VERSION 5.7 ;
BUSBITCHARS "[]" ;
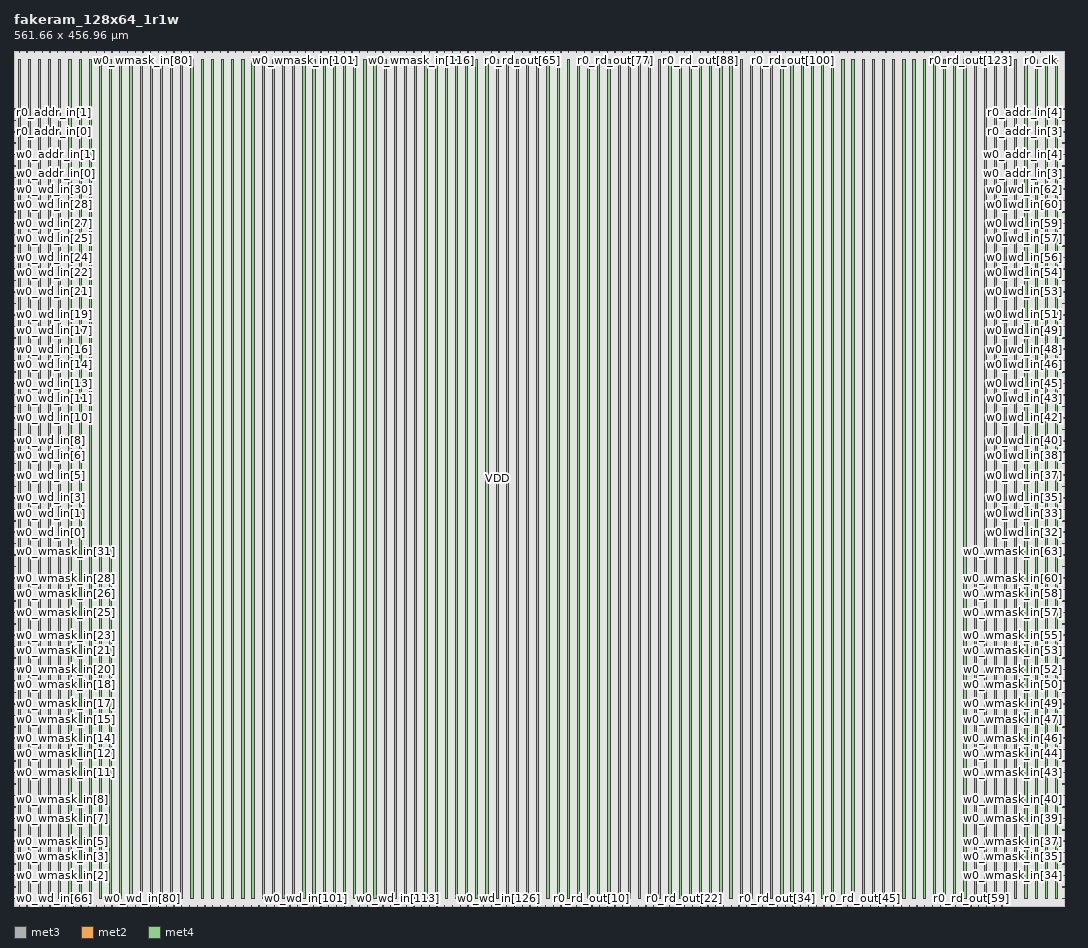
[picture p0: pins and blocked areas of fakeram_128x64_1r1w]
MACRO fakeram_128x64_1r1w
  FOREIGN fakeram_128x64_1r1w 0 0 ;
  SYMMETRY X Y R90 ;
  SIZE 561.660 BY 456.960 ;
  CLASS BLOCK ;
  PIN w0_wmask_in[0]
    DIRECTION INPUT ;
    USE SIGNAL ;
    SHAPE ABUTMENT ;
    PORT
      LAYER met3 ;
      RECT 0.000 3.930 0.900 4.230 ;
    END
  END w0_wmask_in[0]
  PIN w0_wmask_in[1]
    DIRECTION INPUT ;
    USE SIGNAL ;
    SHAPE ABUTMENT ;
    PORT
      LAYER met3 ;
      RECT 0.000 10.050 0.900 10.350 ;
    END
  END w0_wmask_in[1]
  PIN w0_wmask_in[2]
    DIRECTION INPUT ;
    USE SIGNAL ;
    SHAPE ABUTMENT ;
    PORT
      LAYER met3 ;
      RECT 0.000 16.170 0.900 16.470 ;
    END
  END w0_wmask_in[2]
  PIN w0_wmask_in[3]
    DIRECTION INPUT ;
    USE SIGNAL ;
    SHAPE ABUTMENT ;
    PORT
      LAYER met3 ;
      RECT 0.000 22.290 0.900 22.590 ;
    END
  END w0_wmask_in[3]
  PIN w0_wmask_in[4]
    DIRECTION INPUT ;
    USE SIGNAL ;
    SHAPE ABUTMENT ;
    PORT
      LAYER met3 ;
      RECT 0.000 28.410 0.900 28.710 ;
    END
  END w0_wmask_in[4]
  PIN w0_wmask_in[5]
    DIRECTION INPUT ;
    USE SIGNAL ;
    SHAPE ABUTMENT ;
    PORT
      LAYER met3 ;
      RECT 0.000 34.530 0.900 34.830 ;
    END
  END w0_wmask_in[5]
  PIN w0_wmask_in[6]
    DIRECTION INPUT ;
    USE SIGNAL ;
    SHAPE ABUTMENT ;
    PORT
      LAYER met3 ;
      RECT 0.000 40.650 0.900 40.950 ;
    END
  END w0_wmask_in[6]
  PIN w0_wmask_in[7]
    DIRECTION INPUT ;
    USE SIGNAL ;
    SHAPE ABUTMENT ;
    PORT
      LAYER met3 ;
      RECT 0.000 46.770 0.900 47.070 ;
    END
  END w0_wmask_in[7]
  PIN w0_wmask_in[8]
    DIRECTION INPUT ;
    USE SIGNAL ;
    SHAPE ABUTMENT ;
    PORT
      LAYER met3 ;
      RECT 0.000 52.890 0.900 53.190 ;
    END
  END w0_wmask_in[8]
  PIN w0_wmask_in[9]
    DIRECTION INPUT ;
    USE SIGNAL ;
    SHAPE ABUTMENT ;
    PORT
      LAYER met3 ;
      RECT 0.000 59.010 0.900 59.310 ;
    END
  END w0_wmask_in[9]
  PIN w0_wmask_in[10]
    DIRECTION INPUT ;
    USE SIGNAL ;
    SHAPE ABUTMENT ;
    PORT
      LAYER met3 ;
      RECT 0.000 65.130 0.900 65.430 ;
    END
  END w0_wmask_in[10]
  PIN w0_wmask_in[11]
    DIRECTION INPUT ;
    USE SIGNAL ;
    SHAPE ABUTMENT ;
    PORT
      LAYER met3 ;
      RECT 0.000 71.250 0.900 71.550 ;
    END
  END w0_wmask_in[11]
  PIN w0_wmask_in[12]
    DIRECTION INPUT ;
    USE SIGNAL ;
    SHAPE ABUTMENT ;
    PORT
      LAYER met3 ;
      RECT 0.000 77.370 0.900 77.670 ;
    END
  END w0_wmask_in[12]
  PIN w0_wmask_in[13]
    DIRECTION INPUT ;
    USE SIGNAL ;
    SHAPE ABUTMENT ;
    PORT
      LAYER met3 ;
      RECT 0.000 83.490 0.900 83.790 ;
    END
  END w0_wmask_in[13]
  PIN w0_wmask_in[14]
    DIRECTION INPUT ;
    USE SIGNAL ;
    SHAPE ABUTMENT ;
    PORT
      LAYER met3 ;
      RECT 0.000 89.610 0.900 89.910 ;
    END
  END w0_wmask_in[14]
  PIN w0_wmask_in[15]
    DIRECTION INPUT ;
    USE SIGNAL ;
    SHAPE ABUTMENT ;
    PORT
      LAYER met3 ;
      RECT 0.000 95.730 0.900 96.030 ;
    END
  END w0_wmask_in[15]
  PIN w0_wmask_in[16]
    DIRECTION INPUT ;
    USE SIGNAL ;
    SHAPE ABUTMENT ;
    PORT
      LAYER met3 ;
      RECT 0.000 101.850 0.900 102.150 ;
    END
  END w0_wmask_in[16]
  PIN w0_wmask_in[17]
    DIRECTION INPUT ;
    USE SIGNAL ;
    SHAPE ABUTMENT ;
    PORT
      LAYER met3 ;
      RECT 0.000 107.970 0.900 108.270 ;
    END
  END w0_wmask_in[17]
  PIN w0_wmask_in[18]
    DIRECTION INPUT ;
    USE SIGNAL ;
    SHAPE ABUTMENT ;
    PORT
      LAYER met3 ;
      RECT 0.000 114.090 0.900 114.390 ;
    END
  END w0_wmask_in[18]
  PIN w0_wmask_in[19]
    DIRECTION INPUT ;
    USE SIGNAL ;
    SHAPE ABUTMENT ;
    PORT
      LAYER met3 ;
      RECT 0.000 120.210 0.900 120.510 ;
    END
  END w0_wmask_in[19]
  PIN w0_wmask_in[20]
    DIRECTION INPUT ;
    USE SIGNAL ;
    SHAPE ABUTMENT ;
    PORT
      LAYER met3 ;
      RECT 0.000 126.330 0.900 126.630 ;
    END
  END w0_wmask_in[20]
  PIN w0_wmask_in[21]
    DIRECTION INPUT ;
    USE SIGNAL ;
    SHAPE ABUTMENT ;
    PORT
      LAYER met3 ;
      RECT 0.000 132.450 0.900 132.750 ;
    END
  END w0_wmask_in[21]
  PIN w0_wmask_in[22]
    DIRECTION INPUT ;
    USE SIGNAL ;
    SHAPE ABUTMENT ;
    PORT
      LAYER met3 ;
      RECT 0.000 138.570 0.900 138.870 ;
    END
  END w0_wmask_in[22]
  PIN w0_wmask_in[23]
    DIRECTION INPUT ;
    USE SIGNAL ;
    SHAPE ABUTMENT ;
    PORT
      LAYER met3 ;
      RECT 0.000 144.690 0.900 144.990 ;
    END
  END w0_wmask_in[23]
  PIN w0_wmask_in[24]
    DIRECTION INPUT ;
    USE SIGNAL ;
    SHAPE ABUTMENT ;
    PORT
      LAYER met3 ;
      RECT 0.000 150.810 0.900 151.110 ;
    END
  END w0_wmask_in[24]
  PIN w0_wmask_in[25]
    DIRECTION INPUT ;
    USE SIGNAL ;
    SHAPE ABUTMENT ;
    PORT
      LAYER met3 ;
      RECT 0.000 156.930 0.900 157.230 ;
    END
  END w0_wmask_in[25]
  PIN w0_wmask_in[26]
    DIRECTION INPUT ;
    USE SIGNAL ;
    SHAPE ABUTMENT ;
    PORT
      LAYER met3 ;
      RECT 0.000 163.050 0.900 163.350 ;
    END
  END w0_wmask_in[26]
  PIN w0_wmask_in[27]
    DIRECTION INPUT ;
    USE SIGNAL ;
    SHAPE ABUTMENT ;
    PORT
      LAYER met3 ;
      RECT 0.000 169.170 0.900 169.470 ;
    END
  END w0_wmask_in[27]
  PIN w0_wmask_in[28]
    DIRECTION INPUT ;
    USE SIGNAL ;
    SHAPE ABUTMENT ;
    PORT
      LAYER met3 ;
      RECT 0.000 175.290 0.900 175.590 ;
    END
  END w0_wmask_in[28]
  PIN w0_wmask_in[29]
    DIRECTION INPUT ;
    USE SIGNAL ;
    SHAPE ABUTMENT ;
    PORT
      LAYER met3 ;
      RECT 0.000 181.410 0.900 181.710 ;
    END
  END w0_wmask_in[29]
  PIN w0_wmask_in[30]
    DIRECTION INPUT ;
    USE SIGNAL ;
    SHAPE ABUTMENT ;
    PORT
      LAYER met3 ;
      RECT 0.000 187.530 0.900 187.830 ;
    END
  END w0_wmask_in[30]
  PIN w0_wmask_in[31]
    DIRECTION INPUT ;
    USE SIGNAL ;
    SHAPE ABUTMENT ;
    PORT
      LAYER met3 ;
      RECT 0.000 193.650 0.900 193.950 ;
    END
  END w0_wmask_in[31]
  PIN w0_wmask_in[32]
    DIRECTION INPUT ;
    USE SIGNAL ;
    SHAPE ABUTMENT ;
    PORT
      LAYER met3 ;
      RECT 560.760 3.930 561.660 4.230 ;
    END
  END w0_wmask_in[32]
  PIN w0_wmask_in[33]
    DIRECTION INPUT ;
    USE SIGNAL ;
    SHAPE ABUTMENT ;
    PORT
      LAYER met3 ;
      RECT 560.760 10.050 561.660 10.350 ;
    END
  END w0_wmask_in[33]
  PIN w0_wmask_in[34]
    DIRECTION INPUT ;
    USE SIGNAL ;
    SHAPE ABUTMENT ;
    PORT
      LAYER met3 ;
      RECT 560.760 16.170 561.660 16.470 ;
    END
  END w0_wmask_in[34]
  PIN w0_wmask_in[35]
    DIRECTION INPUT ;
    USE SIGNAL ;
    SHAPE ABUTMENT ;
    PORT
      LAYER met3 ;
      RECT 560.760 22.290 561.660 22.590 ;
    END
  END w0_wmask_in[35]
  PIN w0_wmask_in[36]
    DIRECTION INPUT ;
    USE SIGNAL ;
    SHAPE ABUTMENT ;
    PORT
      LAYER met3 ;
      RECT 560.760 28.410 561.660 28.710 ;
    END
  END w0_wmask_in[36]
  PIN w0_wmask_in[37]
    DIRECTION INPUT ;
    USE SIGNAL ;
    SHAPE ABUTMENT ;
    PORT
      LAYER met3 ;
      RECT 560.760 34.530 561.660 34.830 ;
    END
  END w0_wmask_in[37]
  PIN w0_wmask_in[38]
    DIRECTION INPUT ;
    USE SIGNAL ;
    SHAPE ABUTMENT ;
    PORT
      LAYER met3 ;
      RECT 560.760 40.650 561.660 40.950 ;
    END
  END w0_wmask_in[38]
  PIN w0_wmask_in[39]
    DIRECTION INPUT ;
    USE SIGNAL ;
    SHAPE ABUTMENT ;
    PORT
      LAYER met3 ;
      RECT 560.760 46.770 561.660 47.070 ;
    END
  END w0_wmask_in[39]
  PIN w0_wmask_in[40]
    DIRECTION INPUT ;
    USE SIGNAL ;
    SHAPE ABUTMENT ;
    PORT
      LAYER met3 ;
      RECT 560.760 52.890 561.660 53.190 ;
    END
  END w0_wmask_in[40]
  PIN w0_wmask_in[41]
    DIRECTION INPUT ;
    USE SIGNAL ;
    SHAPE ABUTMENT ;
    PORT
      LAYER met3 ;
      RECT 560.760 59.010 561.660 59.310 ;
    END
  END w0_wmask_in[41]
  PIN w0_wmask_in[42]
    DIRECTION INPUT ;
    USE SIGNAL ;
    SHAPE ABUTMENT ;
    PORT
      LAYER met3 ;
      RECT 560.760 65.130 561.660 65.430 ;
    END
  END w0_wmask_in[42]
  PIN w0_wmask_in[43]
    DIRECTION INPUT ;
    USE SIGNAL ;
    SHAPE ABUTMENT ;
    PORT
      LAYER met3 ;
      RECT 560.760 71.250 561.660 71.550 ;
    END
  END w0_wmask_in[43]
  PIN w0_wmask_in[44]
    DIRECTION INPUT ;
    USE SIGNAL ;
    SHAPE ABUTMENT ;
    PORT
      LAYER met3 ;
      RECT 560.760 77.370 561.660 77.670 ;
    END
  END w0_wmask_in[44]
  PIN w0_wmask_in[45]
    DIRECTION INPUT ;
    USE SIGNAL ;
    SHAPE ABUTMENT ;
    PORT
      LAYER met3 ;
      RECT 560.760 83.490 561.660 83.790 ;
    END
  END w0_wmask_in[45]
  PIN w0_wmask_in[46]
    DIRECTION INPUT ;
    USE SIGNAL ;
    SHAPE ABUTMENT ;
    PORT
      LAYER met3 ;
      RECT 560.760 89.610 561.660 89.910 ;
    END
  END w0_wmask_in[46]
  PIN w0_wmask_in[47]
    DIRECTION INPUT ;
    USE SIGNAL ;
    SHAPE ABUTMENT ;
    PORT
      LAYER met3 ;
      RECT 560.760 95.730 561.660 96.030 ;
    END
  END w0_wmask_in[47]
  PIN w0_wmask_in[48]
    DIRECTION INPUT ;
    USE SIGNAL ;
    SHAPE ABUTMENT ;
    PORT
      LAYER met3 ;
      RECT 560.760 101.850 561.660 102.150 ;
    END
  END w0_wmask_in[48]
  PIN w0_wmask_in[49]
    DIRECTION INPUT ;
    USE SIGNAL ;
    SHAPE ABUTMENT ;
    PORT
      LAYER met3 ;
      RECT 560.760 107.970 561.660 108.270 ;
    END
  END w0_wmask_in[49]
  PIN w0_wmask_in[50]
    DIRECTION INPUT ;
    USE SIGNAL ;
    SHAPE ABUTMENT ;
    PORT
      LAYER met3 ;
      RECT 560.760 114.090 561.660 114.390 ;
    END
  END w0_wmask_in[50]
  PIN w0_wmask_in[51]
    DIRECTION INPUT ;
    USE SIGNAL ;
    SHAPE ABUTMENT ;
    PORT
      LAYER met3 ;
      RECT 560.760 120.210 561.660 120.510 ;
    END
  END w0_wmask_in[51]
  PIN w0_wmask_in[52]
    DIRECTION INPUT ;
    USE SIGNAL ;
    SHAPE ABUTMENT ;
    PORT
      LAYER met3 ;
      RECT 560.760 126.330 561.660 126.630 ;
    END
  END w0_wmask_in[52]
  PIN w0_wmask_in[53]
    DIRECTION INPUT ;
    USE SIGNAL ;
    SHAPE ABUTMENT ;
    PORT
      LAYER met3 ;
      RECT 560.760 132.450 561.660 132.750 ;
    END
  END w0_wmask_in[53]
  PIN w0_wmask_in[54]
    DIRECTION INPUT ;
    USE SIGNAL ;
    SHAPE ABUTMENT ;
    PORT
      LAYER met3 ;
      RECT 560.760 138.570 561.660 138.870 ;
    END
  END w0_wmask_in[54]
  PIN w0_wmask_in[55]
    DIRECTION INPUT ;
    USE SIGNAL ;
    SHAPE ABUTMENT ;
    PORT
      LAYER met3 ;
      RECT 560.760 144.690 561.660 144.990 ;
    END
  END w0_wmask_in[55]
  PIN w0_wmask_in[56]
    DIRECTION INPUT ;
    USE SIGNAL ;
    SHAPE ABUTMENT ;
    PORT
      LAYER met3 ;
      RECT 560.760 150.810 561.660 151.110 ;
    END
  END w0_wmask_in[56]
  PIN w0_wmask_in[57]
    DIRECTION INPUT ;
    USE SIGNAL ;
    SHAPE ABUTMENT ;
    PORT
      LAYER met3 ;
      RECT 560.760 156.930 561.660 157.230 ;
    END
  END w0_wmask_in[57]
  PIN w0_wmask_in[58]
    DIRECTION INPUT ;
    USE SIGNAL ;
    SHAPE ABUTMENT ;
    PORT
      LAYER met3 ;
      RECT 560.760 163.050 561.660 163.350 ;
    END
  END w0_wmask_in[58]
  PIN w0_wmask_in[59]
    DIRECTION INPUT ;
    USE SIGNAL ;
    SHAPE ABUTMENT ;
    PORT
      LAYER met3 ;
      RECT 560.760 169.170 561.660 169.470 ;
    END
  END w0_wmask_in[59]
  PIN w0_wmask_in[60]
    DIRECTION INPUT ;
    USE SIGNAL ;
    SHAPE ABUTMENT ;
    PORT
      LAYER met3 ;
      RECT 560.760 175.290 561.660 175.590 ;
    END
  END w0_wmask_in[60]
  PIN w0_wmask_in[61]
    DIRECTION INPUT ;
    USE SIGNAL ;
    SHAPE ABUTMENT ;
    PORT
      LAYER met3 ;
      RECT 560.760 181.410 561.660 181.710 ;
    END
  END w0_wmask_in[61]
  PIN w0_wmask_in[62]
    DIRECTION INPUT ;
    USE SIGNAL ;
    SHAPE ABUTMENT ;
    PORT
      LAYER met3 ;
      RECT 560.760 187.530 561.660 187.830 ;
    END
  END w0_wmask_in[62]
  PIN w0_wmask_in[63]
    DIRECTION INPUT ;
    USE SIGNAL ;
    SHAPE ABUTMENT ;
    PORT
      LAYER met3 ;
      RECT 560.760 193.650 561.660 193.950 ;
    END
  END w0_wmask_in[63]
  PIN w0_wmask_in[64]
    DIRECTION INPUT ;
    USE SIGNAL ;
    SHAPE ABUTMENT ;
    PORT
      LAYER met2 ;
      RECT 2.690 456.540 2.830 456.960 ;
    END
  END w0_wmask_in[64]
  PIN w0_wmask_in[65]
    DIRECTION INPUT ;
    USE SIGNAL ;
    SHAPE ABUTMENT ;
    PORT
      LAYER met2 ;
      RECT 6.830 456.540 6.970 456.960 ;
    END
  END w0_wmask_in[65]
  PIN w0_wmask_in[66]
    DIRECTION INPUT ;
    USE SIGNAL ;
    SHAPE ABUTMENT ;
    PORT
      LAYER met2 ;
      RECT 10.970 456.540 11.110 456.960 ;
    END
  END w0_wmask_in[66]
  PIN w0_wmask_in[67]
    DIRECTION INPUT ;
    USE SIGNAL ;
    SHAPE ABUTMENT ;
    PORT
      LAYER met2 ;
      RECT 15.110 456.540 15.250 456.960 ;
    END
  END w0_wmask_in[67]
  PIN w0_wmask_in[68]
    DIRECTION INPUT ;
    USE SIGNAL ;
    SHAPE ABUTMENT ;
    PORT
      LAYER met2 ;
      RECT 19.250 456.540 19.390 456.960 ;
    END
  END w0_wmask_in[68]
  PIN w0_wmask_in[69]
    DIRECTION INPUT ;
    USE SIGNAL ;
    SHAPE ABUTMENT ;
    PORT
      LAYER met2 ;
      RECT 23.390 456.540 23.530 456.960 ;
    END
  END w0_wmask_in[69]
  PIN w0_wmask_in[70]
    DIRECTION INPUT ;
    USE SIGNAL ;
    SHAPE ABUTMENT ;
    PORT
      LAYER met2 ;
      RECT 27.530 456.540 27.670 456.960 ;
    END
  END w0_wmask_in[70]
  PIN w0_wmask_in[71]
    DIRECTION INPUT ;
    USE SIGNAL ;
    SHAPE ABUTMENT ;
    PORT
      LAYER met2 ;
      RECT 31.670 456.540 31.810 456.960 ;
    END
  END w0_wmask_in[71]
  PIN w0_wmask_in[72]
    DIRECTION INPUT ;
    USE SIGNAL ;
    SHAPE ABUTMENT ;
    PORT
      LAYER met2 ;
      RECT 35.810 456.540 35.950 456.960 ;
    END
  END w0_wmask_in[72]
  PIN w0_wmask_in[73]
    DIRECTION INPUT ;
    USE SIGNAL ;
    SHAPE ABUTMENT ;
    PORT
      LAYER met2 ;
      RECT 39.950 456.540 40.090 456.960 ;
    END
  END w0_wmask_in[73]
  PIN w0_wmask_in[74]
    DIRECTION INPUT ;
    USE SIGNAL ;
    SHAPE ABUTMENT ;
    PORT
      LAYER met2 ;
      RECT 44.090 456.540 44.230 456.960 ;
    END
  END w0_wmask_in[74]
  PIN w0_wmask_in[75]
    DIRECTION INPUT ;
    USE SIGNAL ;
    SHAPE ABUTMENT ;
    PORT
      LAYER met2 ;
      RECT 48.230 456.540 48.370 456.960 ;
    END
  END w0_wmask_in[75]
  PIN w0_wmask_in[76]
    DIRECTION INPUT ;
    USE SIGNAL ;
    SHAPE ABUTMENT ;
    PORT
      LAYER met2 ;
      RECT 52.370 456.540 52.510 456.960 ;
    END
  END w0_wmask_in[76]
  PIN w0_wmask_in[77]
    DIRECTION INPUT ;
    USE SIGNAL ;
    SHAPE ABUTMENT ;
    PORT
      LAYER met2 ;
      RECT 56.510 456.540 56.650 456.960 ;
    END
  END w0_wmask_in[77]
  PIN w0_wmask_in[78]
    DIRECTION INPUT ;
    USE SIGNAL ;
    SHAPE ABUTMENT ;
    PORT
      LAYER met2 ;
      RECT 60.650 456.540 60.790 456.960 ;
    END
  END w0_wmask_in[78]
  PIN w0_wmask_in[79]
    DIRECTION INPUT ;
    USE SIGNAL ;
    SHAPE ABUTMENT ;
    PORT
      LAYER met2 ;
      RECT 64.790 456.540 64.930 456.960 ;
    END
  END w0_wmask_in[79]
  PIN w0_wmask_in[80]
    DIRECTION INPUT ;
    USE SIGNAL ;
    SHAPE ABUTMENT ;
    PORT
      LAYER met2 ;
      RECT 68.930 456.540 69.070 456.960 ;
    END
  END w0_wmask_in[80]
  PIN w0_wmask_in[81]
    DIRECTION INPUT ;
    USE SIGNAL ;
    SHAPE ABUTMENT ;
    PORT
      LAYER met2 ;
      RECT 73.070 456.540 73.210 456.960 ;
    END
  END w0_wmask_in[81]
  PIN w0_wmask_in[82]
    DIRECTION INPUT ;
    USE SIGNAL ;
    SHAPE ABUTMENT ;
    PORT
      LAYER met2 ;
      RECT 77.210 456.540 77.350 456.960 ;
    END
  END w0_wmask_in[82]
  PIN w0_wmask_in[83]
    DIRECTION INPUT ;
    USE SIGNAL ;
    SHAPE ABUTMENT ;
    PORT
      LAYER met2 ;
      RECT 81.350 456.540 81.490 456.960 ;
    END
  END w0_wmask_in[83]
  PIN w0_wmask_in[84]
    DIRECTION INPUT ;
    USE SIGNAL ;
    SHAPE ABUTMENT ;
    PORT
      LAYER met2 ;
      RECT 85.490 456.540 85.630 456.960 ;
    END
  END w0_wmask_in[84]
  PIN w0_wmask_in[85]
    DIRECTION INPUT ;
    USE SIGNAL ;
    SHAPE ABUTMENT ;
    PORT
      LAYER met2 ;
      RECT 89.630 456.540 89.770 456.960 ;
    END
  END w0_wmask_in[85]
  PIN w0_wmask_in[86]
    DIRECTION INPUT ;
    USE SIGNAL ;
    SHAPE ABUTMENT ;
    PORT
      LAYER met2 ;
      RECT 93.770 456.540 93.910 456.960 ;
    END
  END w0_wmask_in[86]
  PIN w0_wmask_in[87]
    DIRECTION INPUT ;
    USE SIGNAL ;
    SHAPE ABUTMENT ;
    PORT
      LAYER met2 ;
      RECT 97.910 456.540 98.050 456.960 ;
    END
  END w0_wmask_in[87]
  PIN w0_wmask_in[88]
    DIRECTION INPUT ;
    USE SIGNAL ;
    SHAPE ABUTMENT ;
    PORT
      LAYER met2 ;
      RECT 102.050 456.540 102.190 456.960 ;
    END
  END w0_wmask_in[88]
  PIN w0_wmask_in[89]
    DIRECTION INPUT ;
    USE SIGNAL ;
    SHAPE ABUTMENT ;
    PORT
      LAYER met2 ;
      RECT 106.190 456.540 106.330 456.960 ;
    END
  END w0_wmask_in[89]
  PIN w0_wmask_in[90]
    DIRECTION INPUT ;
    USE SIGNAL ;
    SHAPE ABUTMENT ;
    PORT
      LAYER met2 ;
      RECT 110.330 456.540 110.470 456.960 ;
    END
  END w0_wmask_in[90]
  PIN w0_wmask_in[91]
    DIRECTION INPUT ;
    USE SIGNAL ;
    SHAPE ABUTMENT ;
    PORT
      LAYER met2 ;
      RECT 114.470 456.540 114.610 456.960 ;
    END
  END w0_wmask_in[91]
  PIN w0_wmask_in[92]
    DIRECTION INPUT ;
    USE SIGNAL ;
    SHAPE ABUTMENT ;
    PORT
      LAYER met2 ;
      RECT 118.610 456.540 118.750 456.960 ;
    END
  END w0_wmask_in[92]
  PIN w0_wmask_in[93]
    DIRECTION INPUT ;
    USE SIGNAL ;
    SHAPE ABUTMENT ;
    PORT
      LAYER met2 ;
      RECT 122.750 456.540 122.890 456.960 ;
    END
  END w0_wmask_in[93]
  PIN w0_wmask_in[94]
    DIRECTION INPUT ;
    USE SIGNAL ;
    SHAPE ABUTMENT ;
    PORT
      LAYER met2 ;
      RECT 126.890 456.540 127.030 456.960 ;
    END
  END w0_wmask_in[94]
  PIN w0_wmask_in[95]
    DIRECTION INPUT ;
    USE SIGNAL ;
    SHAPE ABUTMENT ;
    PORT
      LAYER met2 ;
      RECT 131.030 456.540 131.170 456.960 ;
    END
  END w0_wmask_in[95]
  PIN w0_wmask_in[96]
    DIRECTION INPUT ;
    USE SIGNAL ;
    SHAPE ABUTMENT ;
    PORT
      LAYER met2 ;
      RECT 135.170 456.540 135.310 456.960 ;
    END
  END w0_wmask_in[96]
  PIN w0_wmask_in[97]
    DIRECTION INPUT ;
    USE SIGNAL ;
    SHAPE ABUTMENT ;
    PORT
      LAYER met2 ;
      RECT 139.310 456.540 139.450 456.960 ;
    END
  END w0_wmask_in[97]
  PIN w0_wmask_in[98]
    DIRECTION INPUT ;
    USE SIGNAL ;
    SHAPE ABUTMENT ;
    PORT
      LAYER met2 ;
      RECT 143.450 456.540 143.590 456.960 ;
    END
  END w0_wmask_in[98]
  PIN w0_wmask_in[99]
    DIRECTION INPUT ;
    USE SIGNAL ;
    SHAPE ABUTMENT ;
    PORT
      LAYER met2 ;
      RECT 147.590 456.540 147.730 456.960 ;
    END
  END w0_wmask_in[99]
  PIN w0_wmask_in[100]
    DIRECTION INPUT ;
    USE SIGNAL ;
    SHAPE ABUTMENT ;
    PORT
      LAYER met2 ;
      RECT 151.730 456.540 151.870 456.960 ;
    END
  END w0_wmask_in[100]
  PIN w0_wmask_in[101]
    DIRECTION INPUT ;
    USE SIGNAL ;
    SHAPE ABUTMENT ;
    PORT
      LAYER met2 ;
      RECT 155.870 456.540 156.010 456.960 ;
    END
  END w0_wmask_in[101]
  PIN w0_wmask_in[102]
    DIRECTION INPUT ;
    USE SIGNAL ;
    SHAPE ABUTMENT ;
    PORT
      LAYER met2 ;
      RECT 160.010 456.540 160.150 456.960 ;
    END
  END w0_wmask_in[102]
  PIN w0_wmask_in[103]
    DIRECTION INPUT ;
    USE SIGNAL ;
    SHAPE ABUTMENT ;
    PORT
      LAYER met2 ;
      RECT 164.150 456.540 164.290 456.960 ;
    END
  END w0_wmask_in[103]
  PIN w0_wmask_in[104]
    DIRECTION INPUT ;
    USE SIGNAL ;
    SHAPE ABUTMENT ;
    PORT
      LAYER met2 ;
      RECT 168.290 456.540 168.430 456.960 ;
    END
  END w0_wmask_in[104]
  PIN w0_wmask_in[105]
    DIRECTION INPUT ;
    USE SIGNAL ;
    SHAPE ABUTMENT ;
    PORT
      LAYER met2 ;
      RECT 172.430 456.540 172.570 456.960 ;
    END
  END w0_wmask_in[105]
  PIN w0_wmask_in[106]
    DIRECTION INPUT ;
    USE SIGNAL ;
    SHAPE ABUTMENT ;
    PORT
      LAYER met2 ;
      RECT 176.570 456.540 176.710 456.960 ;
    END
  END w0_wmask_in[106]
  PIN w0_wmask_in[107]
    DIRECTION INPUT ;
    USE SIGNAL ;
    SHAPE ABUTMENT ;
    PORT
      LAYER met2 ;
      RECT 180.710 456.540 180.850 456.960 ;
    END
  END w0_wmask_in[107]
  PIN w0_wmask_in[108]
    DIRECTION INPUT ;
    USE SIGNAL ;
    SHAPE ABUTMENT ;
    PORT
      LAYER met2 ;
      RECT 184.850 456.540 184.990 456.960 ;
    END
  END w0_wmask_in[108]
  PIN w0_wmask_in[109]
    DIRECTION INPUT ;
    USE SIGNAL ;
    SHAPE ABUTMENT ;
    PORT
      LAYER met2 ;
      RECT 188.990 456.540 189.130 456.960 ;
    END
  END w0_wmask_in[109]
  PIN w0_wmask_in[110]
    DIRECTION INPUT ;
    USE SIGNAL ;
    SHAPE ABUTMENT ;
    PORT
      LAYER met2 ;
      RECT 193.130 456.540 193.270 456.960 ;
    END
  END w0_wmask_in[110]
  PIN w0_wmask_in[111]
    DIRECTION INPUT ;
    USE SIGNAL ;
    SHAPE ABUTMENT ;
    PORT
      LAYER met2 ;
      RECT 197.270 456.540 197.410 456.960 ;
    END
  END w0_wmask_in[111]
  PIN w0_wmask_in[112]
    DIRECTION INPUT ;
    USE SIGNAL ;
    SHAPE ABUTMENT ;
    PORT
      LAYER met2 ;
      RECT 201.410 456.540 201.550 456.960 ;
    END
  END w0_wmask_in[112]
  PIN w0_wmask_in[113]
    DIRECTION INPUT ;
    USE SIGNAL ;
    SHAPE ABUTMENT ;
    PORT
      LAYER met2 ;
      RECT 205.550 456.540 205.690 456.960 ;
    END
  END w0_wmask_in[113]
  PIN w0_wmask_in[114]
    DIRECTION INPUT ;
    USE SIGNAL ;
    SHAPE ABUTMENT ;
    PORT
      LAYER met2 ;
      RECT 209.690 456.540 209.830 456.960 ;
    END
  END w0_wmask_in[114]
  PIN w0_wmask_in[115]
    DIRECTION INPUT ;
    USE SIGNAL ;
    SHAPE ABUTMENT ;
    PORT
      LAYER met2 ;
      RECT 213.830 456.540 213.970 456.960 ;
    END
  END w0_wmask_in[115]
  PIN w0_wmask_in[116]
    DIRECTION INPUT ;
    USE SIGNAL ;
    SHAPE ABUTMENT ;
    PORT
      LAYER met2 ;
      RECT 217.970 456.540 218.110 456.960 ;
    END
  END w0_wmask_in[116]
  PIN w0_wmask_in[117]
    DIRECTION INPUT ;
    USE SIGNAL ;
    SHAPE ABUTMENT ;
    PORT
      LAYER met2 ;
      RECT 222.110 456.540 222.250 456.960 ;
    END
  END w0_wmask_in[117]
  PIN w0_wmask_in[118]
    DIRECTION INPUT ;
    USE SIGNAL ;
    SHAPE ABUTMENT ;
    PORT
      LAYER met2 ;
      RECT 226.250 456.540 226.390 456.960 ;
    END
  END w0_wmask_in[118]
  PIN w0_wmask_in[119]
    DIRECTION INPUT ;
    USE SIGNAL ;
    SHAPE ABUTMENT ;
    PORT
      LAYER met2 ;
      RECT 230.390 456.540 230.530 456.960 ;
    END
  END w0_wmask_in[119]
  PIN w0_wmask_in[120]
    DIRECTION INPUT ;
    USE SIGNAL ;
    SHAPE ABUTMENT ;
    PORT
      LAYER met2 ;
      RECT 234.530 456.540 234.670 456.960 ;
    END
  END w0_wmask_in[120]
  PIN w0_wmask_in[121]
    DIRECTION INPUT ;
    USE SIGNAL ;
    SHAPE ABUTMENT ;
    PORT
      LAYER met2 ;
      RECT 238.670 456.540 238.810 456.960 ;
    END
  END w0_wmask_in[121]
  PIN w0_wmask_in[122]
    DIRECTION INPUT ;
    USE SIGNAL ;
    SHAPE ABUTMENT ;
    PORT
      LAYER met2 ;
      RECT 242.810 456.540 242.950 456.960 ;
    END
  END w0_wmask_in[122]
  PIN w0_wmask_in[123]
    DIRECTION INPUT ;
    USE SIGNAL ;
    SHAPE ABUTMENT ;
    PORT
      LAYER met2 ;
      RECT 246.950 456.540 247.090 456.960 ;
    END
  END w0_wmask_in[123]
  PIN w0_wmask_in[124]
    DIRECTION INPUT ;
    USE SIGNAL ;
    SHAPE ABUTMENT ;
    PORT
      LAYER met2 ;
      RECT 251.090 456.540 251.230 456.960 ;
    END
  END w0_wmask_in[124]
  PIN w0_wmask_in[125]
    DIRECTION INPUT ;
    USE SIGNAL ;
    SHAPE ABUTMENT ;
    PORT
      LAYER met2 ;
      RECT 255.230 456.540 255.370 456.960 ;
    END
  END w0_wmask_in[125]
  PIN w0_wmask_in[126]
    DIRECTION INPUT ;
    USE SIGNAL ;
    SHAPE ABUTMENT ;
    PORT
      LAYER met2 ;
      RECT 259.370 456.540 259.510 456.960 ;
    END
  END w0_wmask_in[126]
  PIN w0_wmask_in[127]
    DIRECTION INPUT ;
    USE SIGNAL ;
    SHAPE ABUTMENT ;
    PORT
      LAYER met2 ;
      RECT 263.510 456.540 263.650 456.960 ;
    END
  END w0_wmask_in[127]
  PIN w0_wd_in[0]
    DIRECTION INPUT ;
    USE SIGNAL ;
    SHAPE ABUTMENT ;
    PORT
      LAYER met3 ;
      RECT 0.000 199.770 0.900 200.070 ;
    END
  END w0_wd_in[0]
  PIN w0_wd_in[1]
    DIRECTION INPUT ;
    USE SIGNAL ;
    SHAPE ABUTMENT ;
    PORT
      LAYER met3 ;
      RECT 0.000 205.890 0.900 206.190 ;
    END
  END w0_wd_in[1]
  PIN w0_wd_in[2]
    DIRECTION INPUT ;
    USE SIGNAL ;
    SHAPE ABUTMENT ;
    PORT
      LAYER met3 ;
      RECT 0.000 212.010 0.900 212.310 ;
    END
  END w0_wd_in[2]
  PIN w0_wd_in[3]
    DIRECTION INPUT ;
    USE SIGNAL ;
    SHAPE ABUTMENT ;
    PORT
      LAYER met3 ;
      RECT 0.000 218.130 0.900 218.430 ;
    END
  END w0_wd_in[3]
  PIN w0_wd_in[4]
    DIRECTION INPUT ;
    USE SIGNAL ;
    SHAPE ABUTMENT ;
    PORT
      LAYER met3 ;
      RECT 0.000 224.250 0.900 224.550 ;
    END
  END w0_wd_in[4]
  PIN w0_wd_in[5]
    DIRECTION INPUT ;
    USE SIGNAL ;
    SHAPE ABUTMENT ;
    PORT
      LAYER met3 ;
      RECT 0.000 230.370 0.900 230.670 ;
    END
  END w0_wd_in[5]
  PIN w0_wd_in[6]
    DIRECTION INPUT ;
    USE SIGNAL ;
    SHAPE ABUTMENT ;
    PORT
      LAYER met3 ;
      RECT 0.000 236.490 0.900 236.790 ;
    END
  END w0_wd_in[6]
  PIN w0_wd_in[7]
    DIRECTION INPUT ;
    USE SIGNAL ;
    SHAPE ABUTMENT ;
    PORT
      LAYER met3 ;
      RECT 0.000 242.610 0.900 242.910 ;
    END
  END w0_wd_in[7]
  PIN w0_wd_in[8]
    DIRECTION INPUT ;
    USE SIGNAL ;
    SHAPE ABUTMENT ;
    PORT
      LAYER met3 ;
      RECT 0.000 248.730 0.900 249.030 ;
    END
  END w0_wd_in[8]
  PIN w0_wd_in[9]
    DIRECTION INPUT ;
    USE SIGNAL ;
    SHAPE ABUTMENT ;
    PORT
      LAYER met3 ;
      RECT 0.000 254.850 0.900 255.150 ;
    END
  END w0_wd_in[9]
  PIN w0_wd_in[10]
    DIRECTION INPUT ;
    USE SIGNAL ;
    SHAPE ABUTMENT ;
    PORT
      LAYER met3 ;
      RECT 0.000 260.970 0.900 261.270 ;
    END
  END w0_wd_in[10]
  PIN w0_wd_in[11]
    DIRECTION INPUT ;
    USE SIGNAL ;
    SHAPE ABUTMENT ;
    PORT
      LAYER met3 ;
      RECT 0.000 267.090 0.900 267.390 ;
    END
  END w0_wd_in[11]
  PIN w0_wd_in[12]
    DIRECTION INPUT ;
    USE SIGNAL ;
    SHAPE ABUTMENT ;
    PORT
      LAYER met3 ;
      RECT 0.000 273.210 0.900 273.510 ;
    END
  END w0_wd_in[12]
  PIN w0_wd_in[13]
    DIRECTION INPUT ;
    USE SIGNAL ;
    SHAPE ABUTMENT ;
    PORT
      LAYER met3 ;
      RECT 0.000 279.330 0.900 279.630 ;
    END
  END w0_wd_in[13]
  PIN w0_wd_in[14]
    DIRECTION INPUT ;
    USE SIGNAL ;
    SHAPE ABUTMENT ;
    PORT
      LAYER met3 ;
      RECT 0.000 285.450 0.900 285.750 ;
    END
  END w0_wd_in[14]
  PIN w0_wd_in[15]
    DIRECTION INPUT ;
    USE SIGNAL ;
    SHAPE ABUTMENT ;
    PORT
      LAYER met3 ;
      RECT 0.000 291.570 0.900 291.870 ;
    END
  END w0_wd_in[15]
  PIN w0_wd_in[16]
    DIRECTION INPUT ;
    USE SIGNAL ;
    SHAPE ABUTMENT ;
    PORT
      LAYER met3 ;
      RECT 0.000 297.690 0.900 297.990 ;
    END
  END w0_wd_in[16]
  PIN w0_wd_in[17]
    DIRECTION INPUT ;
    USE SIGNAL ;
    SHAPE ABUTMENT ;
    PORT
      LAYER met3 ;
      RECT 0.000 303.810 0.900 304.110 ;
    END
  END w0_wd_in[17]
  PIN w0_wd_in[18]
    DIRECTION INPUT ;
    USE SIGNAL ;
    SHAPE ABUTMENT ;
    PORT
      LAYER met3 ;
      RECT 0.000 309.930 0.900 310.230 ;
    END
  END w0_wd_in[18]
  PIN w0_wd_in[19]
    DIRECTION INPUT ;
    USE SIGNAL ;
    SHAPE ABUTMENT ;
    PORT
      LAYER met3 ;
      RECT 0.000 316.050 0.900 316.350 ;
    END
  END w0_wd_in[19]
  PIN w0_wd_in[20]
    DIRECTION INPUT ;
    USE SIGNAL ;
    SHAPE ABUTMENT ;
    PORT
      LAYER met3 ;
      RECT 0.000 322.170 0.900 322.470 ;
    END
  END w0_wd_in[20]
  PIN w0_wd_in[21]
    DIRECTION INPUT ;
    USE SIGNAL ;
    SHAPE ABUTMENT ;
    PORT
      LAYER met3 ;
      RECT 0.000 328.290 0.900 328.590 ;
    END
  END w0_wd_in[21]
  PIN w0_wd_in[22]
    DIRECTION INPUT ;
    USE SIGNAL ;
    SHAPE ABUTMENT ;
    PORT
      LAYER met3 ;
      RECT 0.000 334.410 0.900 334.710 ;
    END
  END w0_wd_in[22]
  PIN w0_wd_in[23]
    DIRECTION INPUT ;
    USE SIGNAL ;
    SHAPE ABUTMENT ;
    PORT
      LAYER met3 ;
      RECT 0.000 340.530 0.900 340.830 ;
    END
  END w0_wd_in[23]
  PIN w0_wd_in[24]
    DIRECTION INPUT ;
    USE SIGNAL ;
    SHAPE ABUTMENT ;
    PORT
      LAYER met3 ;
      RECT 0.000 346.650 0.900 346.950 ;
    END
  END w0_wd_in[24]
  PIN w0_wd_in[25]
    DIRECTION INPUT ;
    USE SIGNAL ;
    SHAPE ABUTMENT ;
    PORT
      LAYER met3 ;
      RECT 0.000 352.770 0.900 353.070 ;
    END
  END w0_wd_in[25]
  PIN w0_wd_in[26]
    DIRECTION INPUT ;
    USE SIGNAL ;
    SHAPE ABUTMENT ;
    PORT
      LAYER met3 ;
      RECT 0.000 358.890 0.900 359.190 ;
    END
  END w0_wd_in[26]
  PIN w0_wd_in[27]
    DIRECTION INPUT ;
    USE SIGNAL ;
    SHAPE ABUTMENT ;
    PORT
      LAYER met3 ;
      RECT 0.000 365.010 0.900 365.310 ;
    END
  END w0_wd_in[27]
  PIN w0_wd_in[28]
    DIRECTION INPUT ;
    USE SIGNAL ;
    SHAPE ABUTMENT ;
    PORT
      LAYER met3 ;
      RECT 0.000 371.130 0.900 371.430 ;
    END
  END w0_wd_in[28]
  PIN w0_wd_in[29]
    DIRECTION INPUT ;
    USE SIGNAL ;
    SHAPE ABUTMENT ;
    PORT
      LAYER met3 ;
      RECT 0.000 377.250 0.900 377.550 ;
    END
  END w0_wd_in[29]
  PIN w0_wd_in[30]
    DIRECTION INPUT ;
    USE SIGNAL ;
    SHAPE ABUTMENT ;
    PORT
      LAYER met3 ;
      RECT 0.000 383.370 0.900 383.670 ;
    END
  END w0_wd_in[30]
  PIN w0_wd_in[31]
    DIRECTION INPUT ;
    USE SIGNAL ;
    SHAPE ABUTMENT ;
    PORT
      LAYER met3 ;
      RECT 0.000 389.490 0.900 389.790 ;
    END
  END w0_wd_in[31]
  PIN w0_wd_in[32]
    DIRECTION INPUT ;
    USE SIGNAL ;
    SHAPE ABUTMENT ;
    PORT
      LAYER met3 ;
      RECT 560.760 199.770 561.660 200.070 ;
    END
  END w0_wd_in[32]
  PIN w0_wd_in[33]
    DIRECTION INPUT ;
    USE SIGNAL ;
    SHAPE ABUTMENT ;
    PORT
      LAYER met3 ;
      RECT 560.760 205.890 561.660 206.190 ;
    END
  END w0_wd_in[33]
  PIN w0_wd_in[34]
    DIRECTION INPUT ;
    USE SIGNAL ;
    SHAPE ABUTMENT ;
    PORT
      LAYER met3 ;
      RECT 560.760 212.010 561.660 212.310 ;
    END
  END w0_wd_in[34]
  PIN w0_wd_in[35]
    DIRECTION INPUT ;
    USE SIGNAL ;
    SHAPE ABUTMENT ;
    PORT
      LAYER met3 ;
      RECT 560.760 218.130 561.660 218.430 ;
    END
  END w0_wd_in[35]
  PIN w0_wd_in[36]
    DIRECTION INPUT ;
    USE SIGNAL ;
    SHAPE ABUTMENT ;
    PORT
      LAYER met3 ;
      RECT 560.760 224.250 561.660 224.550 ;
    END
  END w0_wd_in[36]
  PIN w0_wd_in[37]
    DIRECTION INPUT ;
    USE SIGNAL ;
    SHAPE ABUTMENT ;
    PORT
      LAYER met3 ;
      RECT 560.760 230.370 561.660 230.670 ;
    END
  END w0_wd_in[37]
  PIN w0_wd_in[38]
    DIRECTION INPUT ;
    USE SIGNAL ;
    SHAPE ABUTMENT ;
    PORT
      LAYER met3 ;
      RECT 560.760 236.490 561.660 236.790 ;
    END
  END w0_wd_in[38]
  PIN w0_wd_in[39]
    DIRECTION INPUT ;
    USE SIGNAL ;
    SHAPE ABUTMENT ;
    PORT
      LAYER met3 ;
      RECT 560.760 242.610 561.660 242.910 ;
    END
  END w0_wd_in[39]
  PIN w0_wd_in[40]
    DIRECTION INPUT ;
    USE SIGNAL ;
    SHAPE ABUTMENT ;
    PORT
      LAYER met3 ;
      RECT 560.760 248.730 561.660 249.030 ;
    END
  END w0_wd_in[40]
  PIN w0_wd_in[41]
    DIRECTION INPUT ;
    USE SIGNAL ;
    SHAPE ABUTMENT ;
    PORT
      LAYER met3 ;
      RECT 560.760 254.850 561.660 255.150 ;
    END
  END w0_wd_in[41]
  PIN w0_wd_in[42]
    DIRECTION INPUT ;
    USE SIGNAL ;
    SHAPE ABUTMENT ;
    PORT
      LAYER met3 ;
      RECT 560.760 260.970 561.660 261.270 ;
    END
  END w0_wd_in[42]
  PIN w0_wd_in[43]
    DIRECTION INPUT ;
    USE SIGNAL ;
    SHAPE ABUTMENT ;
    PORT
      LAYER met3 ;
      RECT 560.760 267.090 561.660 267.390 ;
    END
  END w0_wd_in[43]
  PIN w0_wd_in[44]
    DIRECTION INPUT ;
    USE SIGNAL ;
    SHAPE ABUTMENT ;
    PORT
      LAYER met3 ;
      RECT 560.760 273.210 561.660 273.510 ;
    END
  END w0_wd_in[44]
  PIN w0_wd_in[45]
    DIRECTION INPUT ;
    USE SIGNAL ;
    SHAPE ABUTMENT ;
    PORT
      LAYER met3 ;
      RECT 560.760 279.330 561.660 279.630 ;
    END
  END w0_wd_in[45]
  PIN w0_wd_in[46]
    DIRECTION INPUT ;
    USE SIGNAL ;
    SHAPE ABUTMENT ;
    PORT
      LAYER met3 ;
      RECT 560.760 285.450 561.660 285.750 ;
    END
  END w0_wd_in[46]
  PIN w0_wd_in[47]
    DIRECTION INPUT ;
    USE SIGNAL ;
    SHAPE ABUTMENT ;
    PORT
      LAYER met3 ;
      RECT 560.760 291.570 561.660 291.870 ;
    END
  END w0_wd_in[47]
  PIN w0_wd_in[48]
    DIRECTION INPUT ;
    USE SIGNAL ;
    SHAPE ABUTMENT ;
    PORT
      LAYER met3 ;
      RECT 560.760 297.690 561.660 297.990 ;
    END
  END w0_wd_in[48]
  PIN w0_wd_in[49]
    DIRECTION INPUT ;
    USE SIGNAL ;
    SHAPE ABUTMENT ;
    PORT
      LAYER met3 ;
      RECT 560.760 303.810 561.660 304.110 ;
    END
  END w0_wd_in[49]
  PIN w0_wd_in[50]
    DIRECTION INPUT ;
    USE SIGNAL ;
    SHAPE ABUTMENT ;
    PORT
      LAYER met3 ;
      RECT 560.760 309.930 561.660 310.230 ;
    END
  END w0_wd_in[50]
  PIN w0_wd_in[51]
    DIRECTION INPUT ;
    USE SIGNAL ;
    SHAPE ABUTMENT ;
    PORT
      LAYER met3 ;
      RECT 560.760 316.050 561.660 316.350 ;
    END
  END w0_wd_in[51]
  PIN w0_wd_in[52]
    DIRECTION INPUT ;
    USE SIGNAL ;
    SHAPE ABUTMENT ;
    PORT
      LAYER met3 ;
      RECT 560.760 322.170 561.660 322.470 ;
    END
  END w0_wd_in[52]
  PIN w0_wd_in[53]
    DIRECTION INPUT ;
    USE SIGNAL ;
    SHAPE ABUTMENT ;
    PORT
      LAYER met3 ;
      RECT 560.760 328.290 561.660 328.590 ;
    END
  END w0_wd_in[53]
  PIN w0_wd_in[54]
    DIRECTION INPUT ;
    USE SIGNAL ;
    SHAPE ABUTMENT ;
    PORT
      LAYER met3 ;
      RECT 560.760 334.410 561.660 334.710 ;
    END
  END w0_wd_in[54]
  PIN w0_wd_in[55]
    DIRECTION INPUT ;
    USE SIGNAL ;
    SHAPE ABUTMENT ;
    PORT
      LAYER met3 ;
      RECT 560.760 340.530 561.660 340.830 ;
    END
  END w0_wd_in[55]
  PIN w0_wd_in[56]
    DIRECTION INPUT ;
    USE SIGNAL ;
    SHAPE ABUTMENT ;
    PORT
      LAYER met3 ;
      RECT 560.760 346.650 561.660 346.950 ;
    END
  END w0_wd_in[56]
  PIN w0_wd_in[57]
    DIRECTION INPUT ;
    USE SIGNAL ;
    SHAPE ABUTMENT ;
    PORT
      LAYER met3 ;
      RECT 560.760 352.770 561.660 353.070 ;
    END
  END w0_wd_in[57]
  PIN w0_wd_in[58]
    DIRECTION INPUT ;
    USE SIGNAL ;
    SHAPE ABUTMENT ;
    PORT
      LAYER met3 ;
      RECT 560.760 358.890 561.660 359.190 ;
    END
  END w0_wd_in[58]
  PIN w0_wd_in[59]
    DIRECTION INPUT ;
    USE SIGNAL ;
    SHAPE ABUTMENT ;
    PORT
      LAYER met3 ;
      RECT 560.760 365.010 561.660 365.310 ;
    END
  END w0_wd_in[59]
  PIN w0_wd_in[60]
    DIRECTION INPUT ;
    USE SIGNAL ;
    SHAPE ABUTMENT ;
    PORT
      LAYER met3 ;
      RECT 560.760 371.130 561.660 371.430 ;
    END
  END w0_wd_in[60]
  PIN w0_wd_in[61]
    DIRECTION INPUT ;
    USE SIGNAL ;
    SHAPE ABUTMENT ;
    PORT
      LAYER met3 ;
      RECT 560.760 377.250 561.660 377.550 ;
    END
  END w0_wd_in[61]
  PIN w0_wd_in[62]
    DIRECTION INPUT ;
    USE SIGNAL ;
    SHAPE ABUTMENT ;
    PORT
      LAYER met3 ;
      RECT 560.760 383.370 561.660 383.670 ;
    END
  END w0_wd_in[62]
  PIN w0_wd_in[63]
    DIRECTION INPUT ;
    USE SIGNAL ;
    SHAPE ABUTMENT ;
    PORT
      LAYER met3 ;
      RECT 560.760 389.490 561.660 389.790 ;
    END
  END w0_wd_in[63]
  PIN w0_wd_in[64]
    DIRECTION INPUT ;
    USE SIGNAL ;
    SHAPE ABUTMENT ;
    PORT
      LAYER met2 ;
      RECT 2.690 0.000 2.830 0.420 ;
    END
  END w0_wd_in[64]
  PIN w0_wd_in[65]
    DIRECTION INPUT ;
    USE SIGNAL ;
    SHAPE ABUTMENT ;
    PORT
      LAYER met2 ;
      RECT 6.830 0.000 6.970 0.420 ;
    END
  END w0_wd_in[65]
  PIN w0_wd_in[66]
    DIRECTION INPUT ;
    USE SIGNAL ;
    SHAPE ABUTMENT ;
    PORT
      LAYER met2 ;
      RECT 10.970 0.000 11.110 0.420 ;
    END
  END w0_wd_in[66]
  PIN w0_wd_in[67]
    DIRECTION INPUT ;
    USE SIGNAL ;
    SHAPE ABUTMENT ;
    PORT
      LAYER met2 ;
      RECT 15.110 0.000 15.250 0.420 ;
    END
  END w0_wd_in[67]
  PIN w0_wd_in[68]
    DIRECTION INPUT ;
    USE SIGNAL ;
    SHAPE ABUTMENT ;
    PORT
      LAYER met2 ;
      RECT 19.250 0.000 19.390 0.420 ;
    END
  END w0_wd_in[68]
  PIN w0_wd_in[69]
    DIRECTION INPUT ;
    USE SIGNAL ;
    SHAPE ABUTMENT ;
    PORT
      LAYER met2 ;
      RECT 23.390 0.000 23.530 0.420 ;
    END
  END w0_wd_in[69]
  PIN w0_wd_in[70]
    DIRECTION INPUT ;
    USE SIGNAL ;
    SHAPE ABUTMENT ;
    PORT
      LAYER met2 ;
      RECT 27.530 0.000 27.670 0.420 ;
    END
  END w0_wd_in[70]
  PIN w0_wd_in[71]
    DIRECTION INPUT ;
    USE SIGNAL ;
    SHAPE ABUTMENT ;
    PORT
      LAYER met2 ;
      RECT 31.670 0.000 31.810 0.420 ;
    END
  END w0_wd_in[71]
  PIN w0_wd_in[72]
    DIRECTION INPUT ;
    USE SIGNAL ;
    SHAPE ABUTMENT ;
    PORT
      LAYER met2 ;
      RECT 35.810 0.000 35.950 0.420 ;
    END
  END w0_wd_in[72]
  PIN w0_wd_in[73]
    DIRECTION INPUT ;
    USE SIGNAL ;
    SHAPE ABUTMENT ;
    PORT
      LAYER met2 ;
      RECT 39.950 0.000 40.090 0.420 ;
    END
  END w0_wd_in[73]
  PIN w0_wd_in[74]
    DIRECTION INPUT ;
    USE SIGNAL ;
    SHAPE ABUTMENT ;
    PORT
      LAYER met2 ;
      RECT 44.090 0.000 44.230 0.420 ;
    END
  END w0_wd_in[74]
  PIN w0_wd_in[75]
    DIRECTION INPUT ;
    USE SIGNAL ;
    SHAPE ABUTMENT ;
    PORT
      LAYER met2 ;
      RECT 48.230 0.000 48.370 0.420 ;
    END
  END w0_wd_in[75]
  PIN w0_wd_in[76]
    DIRECTION INPUT ;
    USE SIGNAL ;
    SHAPE ABUTMENT ;
    PORT
      LAYER met2 ;
      RECT 52.370 0.000 52.510 0.420 ;
    END
  END w0_wd_in[76]
  PIN w0_wd_in[77]
    DIRECTION INPUT ;
    USE SIGNAL ;
    SHAPE ABUTMENT ;
    PORT
      LAYER met2 ;
      RECT 56.510 0.000 56.650 0.420 ;
    END
  END w0_wd_in[77]
  PIN w0_wd_in[78]
    DIRECTION INPUT ;
    USE SIGNAL ;
    SHAPE ABUTMENT ;
    PORT
      LAYER met2 ;
      RECT 60.650 0.000 60.790 0.420 ;
    END
  END w0_wd_in[78]
  PIN w0_wd_in[79]
    DIRECTION INPUT ;
    USE SIGNAL ;
    SHAPE ABUTMENT ;
    PORT
      LAYER met2 ;
      RECT 64.790 0.000 64.930 0.420 ;
    END
  END w0_wd_in[79]
  PIN w0_wd_in[80]
    DIRECTION INPUT ;
    USE SIGNAL ;
    SHAPE ABUTMENT ;
    PORT
      LAYER met2 ;
      RECT 68.930 0.000 69.070 0.420 ;
    END
  END w0_wd_in[80]
  PIN w0_wd_in[81]
    DIRECTION INPUT ;
    USE SIGNAL ;
    SHAPE ABUTMENT ;
    PORT
      LAYER met2 ;
      RECT 73.070 0.000 73.210 0.420 ;
    END
  END w0_wd_in[81]
  PIN w0_wd_in[82]
    DIRECTION INPUT ;
    USE SIGNAL ;
    SHAPE ABUTMENT ;
    PORT
      LAYER met2 ;
      RECT 77.210 0.000 77.350 0.420 ;
    END
  END w0_wd_in[82]
  PIN w0_wd_in[83]
    DIRECTION INPUT ;
    USE SIGNAL ;
    SHAPE ABUTMENT ;
    PORT
      LAYER met2 ;
      RECT 81.350 0.000 81.490 0.420 ;
    END
  END w0_wd_in[83]
  PIN w0_wd_in[84]
    DIRECTION INPUT ;
    USE SIGNAL ;
    SHAPE ABUTMENT ;
    PORT
      LAYER met2 ;
      RECT 85.490 0.000 85.630 0.420 ;
    END
  END w0_wd_in[84]
  PIN w0_wd_in[85]
    DIRECTION INPUT ;
    USE SIGNAL ;
    SHAPE ABUTMENT ;
    PORT
      LAYER met2 ;
      RECT 89.630 0.000 89.770 0.420 ;
    END
  END w0_wd_in[85]
  PIN w0_wd_in[86]
    DIRECTION INPUT ;
    USE SIGNAL ;
    SHAPE ABUTMENT ;
    PORT
      LAYER met2 ;
      RECT 93.770 0.000 93.910 0.420 ;
    END
  END w0_wd_in[86]
  PIN w0_wd_in[87]
    DIRECTION INPUT ;
    USE SIGNAL ;
    SHAPE ABUTMENT ;
    PORT
      LAYER met2 ;
      RECT 97.910 0.000 98.050 0.420 ;
    END
  END w0_wd_in[87]
  PIN w0_wd_in[88]
    DIRECTION INPUT ;
    USE SIGNAL ;
    SHAPE ABUTMENT ;
    PORT
      LAYER met2 ;
      RECT 102.050 0.000 102.190 0.420 ;
    END
  END w0_wd_in[88]
  PIN w0_wd_in[89]
    DIRECTION INPUT ;
    USE SIGNAL ;
    SHAPE ABUTMENT ;
    PORT
      LAYER met2 ;
      RECT 106.190 0.000 106.330 0.420 ;
    END
  END w0_wd_in[89]
  PIN w0_wd_in[90]
    DIRECTION INPUT ;
    USE SIGNAL ;
    SHAPE ABUTMENT ;
    PORT
      LAYER met2 ;
      RECT 110.330 0.000 110.470 0.420 ;
    END
  END w0_wd_in[90]
  PIN w0_wd_in[91]
    DIRECTION INPUT ;
    USE SIGNAL ;
    SHAPE ABUTMENT ;
    PORT
      LAYER met2 ;
      RECT 114.470 0.000 114.610 0.420 ;
    END
  END w0_wd_in[91]
  PIN w0_wd_in[92]
    DIRECTION INPUT ;
    USE SIGNAL ;
    SHAPE ABUTMENT ;
    PORT
      LAYER met2 ;
      RECT 118.610 0.000 118.750 0.420 ;
    END
  END w0_wd_in[92]
  PIN w0_wd_in[93]
    DIRECTION INPUT ;
    USE SIGNAL ;
    SHAPE ABUTMENT ;
    PORT
      LAYER met2 ;
      RECT 122.750 0.000 122.890 0.420 ;
    END
  END w0_wd_in[93]
  PIN w0_wd_in[94]
    DIRECTION INPUT ;
    USE SIGNAL ;
    SHAPE ABUTMENT ;
    PORT
      LAYER met2 ;
      RECT 126.890 0.000 127.030 0.420 ;
    END
  END w0_wd_in[94]
  PIN w0_wd_in[95]
    DIRECTION INPUT ;
    USE SIGNAL ;
    SHAPE ABUTMENT ;
    PORT
      LAYER met2 ;
      RECT 131.030 0.000 131.170 0.420 ;
    END
  END w0_wd_in[95]
  PIN w0_wd_in[96]
    DIRECTION INPUT ;
    USE SIGNAL ;
    SHAPE ABUTMENT ;
    PORT
      LAYER met2 ;
      RECT 135.170 0.000 135.310 0.420 ;
    END
  END w0_wd_in[96]
  PIN w0_wd_in[97]
    DIRECTION INPUT ;
    USE SIGNAL ;
    SHAPE ABUTMENT ;
    PORT
      LAYER met2 ;
      RECT 139.310 0.000 139.450 0.420 ;
    END
  END w0_wd_in[97]
  PIN w0_wd_in[98]
    DIRECTION INPUT ;
    USE SIGNAL ;
    SHAPE ABUTMENT ;
    PORT
      LAYER met2 ;
      RECT 143.450 0.000 143.590 0.420 ;
    END
  END w0_wd_in[98]
  PIN w0_wd_in[99]
    DIRECTION INPUT ;
    USE SIGNAL ;
    SHAPE ABUTMENT ;
    PORT
      LAYER met2 ;
      RECT 147.590 0.000 147.730 0.420 ;
    END
  END w0_wd_in[99]
  PIN w0_wd_in[100]
    DIRECTION INPUT ;
    USE SIGNAL ;
    SHAPE ABUTMENT ;
    PORT
      LAYER met2 ;
      RECT 151.730 0.000 151.870 0.420 ;
    END
  END w0_wd_in[100]
  PIN w0_wd_in[101]
    DIRECTION INPUT ;
    USE SIGNAL ;
    SHAPE ABUTMENT ;
    PORT
      LAYER met2 ;
      RECT 155.870 0.000 156.010 0.420 ;
    END
  END w0_wd_in[101]
  PIN w0_wd_in[102]
    DIRECTION INPUT ;
    USE SIGNAL ;
    SHAPE ABUTMENT ;
    PORT
      LAYER met2 ;
      RECT 160.010 0.000 160.150 0.420 ;
    END
  END w0_wd_in[102]
  PIN w0_wd_in[103]
    DIRECTION INPUT ;
    USE SIGNAL ;
    SHAPE ABUTMENT ;
    PORT
      LAYER met2 ;
      RECT 164.150 0.000 164.290 0.420 ;
    END
  END w0_wd_in[103]
  PIN w0_wd_in[104]
    DIRECTION INPUT ;
    USE SIGNAL ;
    SHAPE ABUTMENT ;
    PORT
      LAYER met2 ;
      RECT 168.290 0.000 168.430 0.420 ;
    END
  END w0_wd_in[104]
  PIN w0_wd_in[105]
    DIRECTION INPUT ;
    USE SIGNAL ;
    SHAPE ABUTMENT ;
    PORT
      LAYER met2 ;
      RECT 172.430 0.000 172.570 0.420 ;
    END
  END w0_wd_in[105]
  PIN w0_wd_in[106]
    DIRECTION INPUT ;
    USE SIGNAL ;
    SHAPE ABUTMENT ;
    PORT
      LAYER met2 ;
      RECT 176.570 0.000 176.710 0.420 ;
    END
  END w0_wd_in[106]
  PIN w0_wd_in[107]
    DIRECTION INPUT ;
    USE SIGNAL ;
    SHAPE ABUTMENT ;
    PORT
      LAYER met2 ;
      RECT 180.710 0.000 180.850 0.420 ;
    END
  END w0_wd_in[107]
  PIN w0_wd_in[108]
    DIRECTION INPUT ;
    USE SIGNAL ;
    SHAPE ABUTMENT ;
    PORT
      LAYER met2 ;
      RECT 184.850 0.000 184.990 0.420 ;
    END
  END w0_wd_in[108]
  PIN w0_wd_in[109]
    DIRECTION INPUT ;
    USE SIGNAL ;
    SHAPE ABUTMENT ;
    PORT
      LAYER met2 ;
      RECT 188.990 0.000 189.130 0.420 ;
    END
  END w0_wd_in[109]
  PIN w0_wd_in[110]
    DIRECTION INPUT ;
    USE SIGNAL ;
    SHAPE ABUTMENT ;
    PORT
      LAYER met2 ;
      RECT 193.130 0.000 193.270 0.420 ;
    END
  END w0_wd_in[110]
  PIN w0_wd_in[111]
    DIRECTION INPUT ;
    USE SIGNAL ;
    SHAPE ABUTMENT ;
    PORT
      LAYER met2 ;
      RECT 197.270 0.000 197.410 0.420 ;
    END
  END w0_wd_in[111]
  PIN w0_wd_in[112]
    DIRECTION INPUT ;
    USE SIGNAL ;
    SHAPE ABUTMENT ;
    PORT
      LAYER met2 ;
      RECT 201.410 0.000 201.550 0.420 ;
    END
  END w0_wd_in[112]
  PIN w0_wd_in[113]
    DIRECTION INPUT ;
    USE SIGNAL ;
    SHAPE ABUTMENT ;
    PORT
      LAYER met2 ;
      RECT 205.550 0.000 205.690 0.420 ;
    END
  END w0_wd_in[113]
  PIN w0_wd_in[114]
    DIRECTION INPUT ;
    USE SIGNAL ;
    SHAPE ABUTMENT ;
    PORT
      LAYER met2 ;
      RECT 209.690 0.000 209.830 0.420 ;
    END
  END w0_wd_in[114]
  PIN w0_wd_in[115]
    DIRECTION INPUT ;
    USE SIGNAL ;
    SHAPE ABUTMENT ;
    PORT
      LAYER met2 ;
      RECT 213.830 0.000 213.970 0.420 ;
    END
  END w0_wd_in[115]
  PIN w0_wd_in[116]
    DIRECTION INPUT ;
    USE SIGNAL ;
    SHAPE ABUTMENT ;
    PORT
      LAYER met2 ;
      RECT 217.970 0.000 218.110 0.420 ;
    END
  END w0_wd_in[116]
  PIN w0_wd_in[117]
    DIRECTION INPUT ;
    USE SIGNAL ;
    SHAPE ABUTMENT ;
    PORT
      LAYER met2 ;
      RECT 222.110 0.000 222.250 0.420 ;
    END
  END w0_wd_in[117]
  PIN w0_wd_in[118]
    DIRECTION INPUT ;
    USE SIGNAL ;
    SHAPE ABUTMENT ;
    PORT
      LAYER met2 ;
      RECT 226.250 0.000 226.390 0.420 ;
    END
  END w0_wd_in[118]
  PIN w0_wd_in[119]
    DIRECTION INPUT ;
    USE SIGNAL ;
    SHAPE ABUTMENT ;
    PORT
      LAYER met2 ;
      RECT 230.390 0.000 230.530 0.420 ;
    END
  END w0_wd_in[119]
  PIN w0_wd_in[120]
    DIRECTION INPUT ;
    USE SIGNAL ;
    SHAPE ABUTMENT ;
    PORT
      LAYER met2 ;
      RECT 234.530 0.000 234.670 0.420 ;
    END
  END w0_wd_in[120]
  PIN w0_wd_in[121]
    DIRECTION INPUT ;
    USE SIGNAL ;
    SHAPE ABUTMENT ;
    PORT
      LAYER met2 ;
      RECT 238.670 0.000 238.810 0.420 ;
    END
  END w0_wd_in[121]
  PIN w0_wd_in[122]
    DIRECTION INPUT ;
    USE SIGNAL ;
    SHAPE ABUTMENT ;
    PORT
      LAYER met2 ;
      RECT 242.810 0.000 242.950 0.420 ;
    END
  END w0_wd_in[122]
  PIN w0_wd_in[123]
    DIRECTION INPUT ;
    USE SIGNAL ;
    SHAPE ABUTMENT ;
    PORT
      LAYER met2 ;
      RECT 246.950 0.000 247.090 0.420 ;
    END
  END w0_wd_in[123]
  PIN w0_wd_in[124]
    DIRECTION INPUT ;
    USE SIGNAL ;
    SHAPE ABUTMENT ;
    PORT
      LAYER met2 ;
      RECT 251.090 0.000 251.230 0.420 ;
    END
  END w0_wd_in[124]
  PIN w0_wd_in[125]
    DIRECTION INPUT ;
    USE SIGNAL ;
    SHAPE ABUTMENT ;
    PORT
      LAYER met2 ;
      RECT 255.230 0.000 255.370 0.420 ;
    END
  END w0_wd_in[125]
  PIN w0_wd_in[126]
    DIRECTION INPUT ;
    USE SIGNAL ;
    SHAPE ABUTMENT ;
    PORT
      LAYER met2 ;
      RECT 259.370 0.000 259.510 0.420 ;
    END
  END w0_wd_in[126]
  PIN w0_wd_in[127]
    DIRECTION INPUT ;
    USE SIGNAL ;
    SHAPE ABUTMENT ;
    PORT
      LAYER met2 ;
      RECT 263.510 0.000 263.650 0.420 ;
    END
  END w0_wd_in[127]
  PIN r0_rd_out[0]
    DIRECTION OUTPUT ;
    USE SIGNAL ;
    SHAPE ABUTMENT ;
    PORT
      LAYER met2 ;
      RECT 267.650 0.000 267.790 0.420 ;
    END
  END r0_rd_out[0]
  PIN r0_rd_out[1]
    DIRECTION OUTPUT ;
    USE SIGNAL ;
    SHAPE ABUTMENT ;
    PORT
      LAYER met2 ;
      RECT 271.790 0.000 271.930 0.420 ;
    END
  END r0_rd_out[1]
  PIN r0_rd_out[2]
    DIRECTION OUTPUT ;
    USE SIGNAL ;
    SHAPE ABUTMENT ;
    PORT
      LAYER met2 ;
      RECT 275.930 0.000 276.070 0.420 ;
    END
  END r0_rd_out[2]
  PIN r0_rd_out[3]
    DIRECTION OUTPUT ;
    USE SIGNAL ;
    SHAPE ABUTMENT ;
    PORT
      LAYER met2 ;
      RECT 280.070 0.000 280.210 0.420 ;
    END
  END r0_rd_out[3]
  PIN r0_rd_out[4]
    DIRECTION OUTPUT ;
    USE SIGNAL ;
    SHAPE ABUTMENT ;
    PORT
      LAYER met2 ;
      RECT 284.210 0.000 284.350 0.420 ;
    END
  END r0_rd_out[4]
  PIN r0_rd_out[5]
    DIRECTION OUTPUT ;
    USE SIGNAL ;
    SHAPE ABUTMENT ;
    PORT
      LAYER met2 ;
      RECT 288.350 0.000 288.490 0.420 ;
    END
  END r0_rd_out[5]
  PIN r0_rd_out[6]
    DIRECTION OUTPUT ;
    USE SIGNAL ;
    SHAPE ABUTMENT ;
    PORT
      LAYER met2 ;
      RECT 292.490 0.000 292.630 0.420 ;
    END
  END r0_rd_out[6]
  PIN r0_rd_out[7]
    DIRECTION OUTPUT ;
    USE SIGNAL ;
    SHAPE ABUTMENT ;
    PORT
      LAYER met2 ;
      RECT 296.630 0.000 296.770 0.420 ;
    END
  END r0_rd_out[7]
  PIN r0_rd_out[8]
    DIRECTION OUTPUT ;
    USE SIGNAL ;
    SHAPE ABUTMENT ;
    PORT
      LAYER met2 ;
      RECT 300.770 0.000 300.910 0.420 ;
    END
  END r0_rd_out[8]
  PIN r0_rd_out[9]
    DIRECTION OUTPUT ;
    USE SIGNAL ;
    SHAPE ABUTMENT ;
    PORT
      LAYER met2 ;
      RECT 304.910 0.000 305.050 0.420 ;
    END
  END r0_rd_out[9]
  PIN r0_rd_out[10]
    DIRECTION OUTPUT ;
    USE SIGNAL ;
    SHAPE ABUTMENT ;
    PORT
      LAYER met2 ;
      RECT 309.050 0.000 309.190 0.420 ;
    END
  END r0_rd_out[10]
  PIN r0_rd_out[11]
    DIRECTION OUTPUT ;
    USE SIGNAL ;
    SHAPE ABUTMENT ;
    PORT
      LAYER met2 ;
      RECT 313.190 0.000 313.330 0.420 ;
    END
  END r0_rd_out[11]
  PIN r0_rd_out[12]
    DIRECTION OUTPUT ;
    USE SIGNAL ;
    SHAPE ABUTMENT ;
    PORT
      LAYER met2 ;
      RECT 317.330 0.000 317.470 0.420 ;
    END
  END r0_rd_out[12]
  PIN r0_rd_out[13]
    DIRECTION OUTPUT ;
    USE SIGNAL ;
    SHAPE ABUTMENT ;
    PORT
      LAYER met2 ;
      RECT 321.470 0.000 321.610 0.420 ;
    END
  END r0_rd_out[13]
  PIN r0_rd_out[14]
    DIRECTION OUTPUT ;
    USE SIGNAL ;
    SHAPE ABUTMENT ;
    PORT
      LAYER met2 ;
      RECT 325.610 0.000 325.750 0.420 ;
    END
  END r0_rd_out[14]
  PIN r0_rd_out[15]
    DIRECTION OUTPUT ;
    USE SIGNAL ;
    SHAPE ABUTMENT ;
    PORT
      LAYER met2 ;
      RECT 329.750 0.000 329.890 0.420 ;
    END
  END r0_rd_out[15]
  PIN r0_rd_out[16]
    DIRECTION OUTPUT ;
    USE SIGNAL ;
    SHAPE ABUTMENT ;
    PORT
      LAYER met2 ;
      RECT 333.890 0.000 334.030 0.420 ;
    END
  END r0_rd_out[16]
  PIN r0_rd_out[17]
    DIRECTION OUTPUT ;
    USE SIGNAL ;
    SHAPE ABUTMENT ;
    PORT
      LAYER met2 ;
      RECT 338.030 0.000 338.170 0.420 ;
    END
  END r0_rd_out[17]
  PIN r0_rd_out[18]
    DIRECTION OUTPUT ;
    USE SIGNAL ;
    SHAPE ABUTMENT ;
    PORT
      LAYER met2 ;
      RECT 342.170 0.000 342.310 0.420 ;
    END
  END r0_rd_out[18]
  PIN r0_rd_out[19]
    DIRECTION OUTPUT ;
    USE SIGNAL ;
    SHAPE ABUTMENT ;
    PORT
      LAYER met2 ;
      RECT 346.310 0.000 346.450 0.420 ;
    END
  END r0_rd_out[19]
  PIN r0_rd_out[20]
    DIRECTION OUTPUT ;
    USE SIGNAL ;
    SHAPE ABUTMENT ;
    PORT
      LAYER met2 ;
      RECT 350.450 0.000 350.590 0.420 ;
    END
  END r0_rd_out[20]
  PIN r0_rd_out[21]
    DIRECTION OUTPUT ;
    USE SIGNAL ;
    SHAPE ABUTMENT ;
    PORT
      LAYER met2 ;
      RECT 354.590 0.000 354.730 0.420 ;
    END
  END r0_rd_out[21]
  PIN r0_rd_out[22]
    DIRECTION OUTPUT ;
    USE SIGNAL ;
    SHAPE ABUTMENT ;
    PORT
      LAYER met2 ;
      RECT 358.730 0.000 358.870 0.420 ;
    END
  END r0_rd_out[22]
  PIN r0_rd_out[23]
    DIRECTION OUTPUT ;
    USE SIGNAL ;
    SHAPE ABUTMENT ;
    PORT
      LAYER met2 ;
      RECT 362.870 0.000 363.010 0.420 ;
    END
  END r0_rd_out[23]
  PIN r0_rd_out[24]
    DIRECTION OUTPUT ;
    USE SIGNAL ;
    SHAPE ABUTMENT ;
    PORT
      LAYER met2 ;
      RECT 367.010 0.000 367.150 0.420 ;
    END
  END r0_rd_out[24]
  PIN r0_rd_out[25]
    DIRECTION OUTPUT ;
    USE SIGNAL ;
    SHAPE ABUTMENT ;
    PORT
      LAYER met2 ;
      RECT 371.150 0.000 371.290 0.420 ;
    END
  END r0_rd_out[25]
  PIN r0_rd_out[26]
    DIRECTION OUTPUT ;
    USE SIGNAL ;
    SHAPE ABUTMENT ;
    PORT
      LAYER met2 ;
      RECT 375.290 0.000 375.430 0.420 ;
    END
  END r0_rd_out[26]
  PIN r0_rd_out[27]
    DIRECTION OUTPUT ;
    USE SIGNAL ;
    SHAPE ABUTMENT ;
    PORT
      LAYER met2 ;
      RECT 379.430 0.000 379.570 0.420 ;
    END
  END r0_rd_out[27]
  PIN r0_rd_out[28]
    DIRECTION OUTPUT ;
    USE SIGNAL ;
    SHAPE ABUTMENT ;
    PORT
      LAYER met2 ;
      RECT 383.570 0.000 383.710 0.420 ;
    END
  END r0_rd_out[28]
  PIN r0_rd_out[29]
    DIRECTION OUTPUT ;
    USE SIGNAL ;
    SHAPE ABUTMENT ;
    PORT
      LAYER met2 ;
      RECT 387.710 0.000 387.850 0.420 ;
    END
  END r0_rd_out[29]
  PIN r0_rd_out[30]
    DIRECTION OUTPUT ;
    USE SIGNAL ;
    SHAPE ABUTMENT ;
    PORT
      LAYER met2 ;
      RECT 391.850 0.000 391.990 0.420 ;
    END
  END r0_rd_out[30]
  PIN r0_rd_out[31]
    DIRECTION OUTPUT ;
    USE SIGNAL ;
    SHAPE ABUTMENT ;
    PORT
      LAYER met2 ;
      RECT 395.990 0.000 396.130 0.420 ;
    END
  END r0_rd_out[31]
  PIN r0_rd_out[32]
    DIRECTION OUTPUT ;
    USE SIGNAL ;
    SHAPE ABUTMENT ;
    PORT
      LAYER met2 ;
      RECT 400.130 0.000 400.270 0.420 ;
    END
  END r0_rd_out[32]
  PIN r0_rd_out[33]
    DIRECTION OUTPUT ;
    USE SIGNAL ;
    SHAPE ABUTMENT ;
    PORT
      LAYER met2 ;
      RECT 404.270 0.000 404.410 0.420 ;
    END
  END r0_rd_out[33]
  PIN r0_rd_out[34]
    DIRECTION OUTPUT ;
    USE SIGNAL ;
    SHAPE ABUTMENT ;
    PORT
      LAYER met2 ;
      RECT 408.410 0.000 408.550 0.420 ;
    END
  END r0_rd_out[34]
  PIN r0_rd_out[35]
    DIRECTION OUTPUT ;
    USE SIGNAL ;
    SHAPE ABUTMENT ;
    PORT
      LAYER met2 ;
      RECT 412.550 0.000 412.690 0.420 ;
    END
  END r0_rd_out[35]
  PIN r0_rd_out[36]
    DIRECTION OUTPUT ;
    USE SIGNAL ;
    SHAPE ABUTMENT ;
    PORT
      LAYER met2 ;
      RECT 416.690 0.000 416.830 0.420 ;
    END
  END r0_rd_out[36]
  PIN r0_rd_out[37]
    DIRECTION OUTPUT ;
    USE SIGNAL ;
    SHAPE ABUTMENT ;
    PORT
      LAYER met2 ;
      RECT 420.830 0.000 420.970 0.420 ;
    END
  END r0_rd_out[37]
  PIN r0_rd_out[38]
    DIRECTION OUTPUT ;
    USE SIGNAL ;
    SHAPE ABUTMENT ;
    PORT
      LAYER met2 ;
      RECT 424.970 0.000 425.110 0.420 ;
    END
  END r0_rd_out[38]
  PIN r0_rd_out[39]
    DIRECTION OUTPUT ;
    USE SIGNAL ;
    SHAPE ABUTMENT ;
    PORT
      LAYER met2 ;
      RECT 429.110 0.000 429.250 0.420 ;
    END
  END r0_rd_out[39]
  PIN r0_rd_out[40]
    DIRECTION OUTPUT ;
    USE SIGNAL ;
    SHAPE ABUTMENT ;
    PORT
      LAYER met2 ;
      RECT 433.250 0.000 433.390 0.420 ;
    END
  END r0_rd_out[40]
  PIN r0_rd_out[41]
    DIRECTION OUTPUT ;
    USE SIGNAL ;
    SHAPE ABUTMENT ;
    PORT
      LAYER met2 ;
      RECT 437.390 0.000 437.530 0.420 ;
    END
  END r0_rd_out[41]
  PIN r0_rd_out[42]
    DIRECTION OUTPUT ;
    USE SIGNAL ;
    SHAPE ABUTMENT ;
    PORT
      LAYER met2 ;
      RECT 441.530 0.000 441.670 0.420 ;
    END
  END r0_rd_out[42]
  PIN r0_rd_out[43]
    DIRECTION OUTPUT ;
    USE SIGNAL ;
    SHAPE ABUTMENT ;
    PORT
      LAYER met2 ;
      RECT 445.670 0.000 445.810 0.420 ;
    END
  END r0_rd_out[43]
  PIN r0_rd_out[44]
    DIRECTION OUTPUT ;
    USE SIGNAL ;
    SHAPE ABUTMENT ;
    PORT
      LAYER met2 ;
      RECT 449.810 0.000 449.950 0.420 ;
    END
  END r0_rd_out[44]
  PIN r0_rd_out[45]
    DIRECTION OUTPUT ;
    USE SIGNAL ;
    SHAPE ABUTMENT ;
    PORT
      LAYER met2 ;
      RECT 453.950 0.000 454.090 0.420 ;
    END
  END r0_rd_out[45]
  PIN r0_rd_out[46]
    DIRECTION OUTPUT ;
    USE SIGNAL ;
    SHAPE ABUTMENT ;
    PORT
      LAYER met2 ;
      RECT 458.090 0.000 458.230 0.420 ;
    END
  END r0_rd_out[46]
  PIN r0_rd_out[47]
    DIRECTION OUTPUT ;
    USE SIGNAL ;
    SHAPE ABUTMENT ;
    PORT
      LAYER met2 ;
      RECT 462.230 0.000 462.370 0.420 ;
    END
  END r0_rd_out[47]
  PIN r0_rd_out[48]
    DIRECTION OUTPUT ;
    USE SIGNAL ;
    SHAPE ABUTMENT ;
    PORT
      LAYER met2 ;
      RECT 466.370 0.000 466.510 0.420 ;
    END
  END r0_rd_out[48]
  PIN r0_rd_out[49]
    DIRECTION OUTPUT ;
    USE SIGNAL ;
    SHAPE ABUTMENT ;
    PORT
      LAYER met2 ;
      RECT 470.510 0.000 470.650 0.420 ;
    END
  END r0_rd_out[49]
  PIN r0_rd_out[50]
    DIRECTION OUTPUT ;
    USE SIGNAL ;
    SHAPE ABUTMENT ;
    PORT
      LAYER met2 ;
      RECT 474.650 0.000 474.790 0.420 ;
    END
  END r0_rd_out[50]
  PIN r0_rd_out[51]
    DIRECTION OUTPUT ;
    USE SIGNAL ;
    SHAPE ABUTMENT ;
    PORT
      LAYER met2 ;
      RECT 478.790 0.000 478.930 0.420 ;
    END
  END r0_rd_out[51]
  PIN r0_rd_out[52]
    DIRECTION OUTPUT ;
    USE SIGNAL ;
    SHAPE ABUTMENT ;
    PORT
      LAYER met2 ;
      RECT 482.930 0.000 483.070 0.420 ;
    END
  END r0_rd_out[52]
  PIN r0_rd_out[53]
    DIRECTION OUTPUT ;
    USE SIGNAL ;
    SHAPE ABUTMENT ;
    PORT
      LAYER met2 ;
      RECT 487.070 0.000 487.210 0.420 ;
    END
  END r0_rd_out[53]
  PIN r0_rd_out[54]
    DIRECTION OUTPUT ;
    USE SIGNAL ;
    SHAPE ABUTMENT ;
    PORT
      LAYER met2 ;
      RECT 491.210 0.000 491.350 0.420 ;
    END
  END r0_rd_out[54]
  PIN r0_rd_out[55]
    DIRECTION OUTPUT ;
    USE SIGNAL ;
    SHAPE ABUTMENT ;
    PORT
      LAYER met2 ;
      RECT 495.350 0.000 495.490 0.420 ;
    END
  END r0_rd_out[55]
  PIN r0_rd_out[56]
    DIRECTION OUTPUT ;
    USE SIGNAL ;
    SHAPE ABUTMENT ;
    PORT
      LAYER met2 ;
      RECT 499.490 0.000 499.630 0.420 ;
    END
  END r0_rd_out[56]
  PIN r0_rd_out[57]
    DIRECTION OUTPUT ;
    USE SIGNAL ;
    SHAPE ABUTMENT ;
    PORT
      LAYER met2 ;
      RECT 503.630 0.000 503.770 0.420 ;
    END
  END r0_rd_out[57]
  PIN r0_rd_out[58]
    DIRECTION OUTPUT ;
    USE SIGNAL ;
    SHAPE ABUTMENT ;
    PORT
      LAYER met2 ;
      RECT 507.770 0.000 507.910 0.420 ;
    END
  END r0_rd_out[58]
  PIN r0_rd_out[59]
    DIRECTION OUTPUT ;
    USE SIGNAL ;
    SHAPE ABUTMENT ;
    PORT
      LAYER met2 ;
      RECT 511.910 0.000 512.050 0.420 ;
    END
  END r0_rd_out[59]
  PIN r0_rd_out[60]
    DIRECTION OUTPUT ;
    USE SIGNAL ;
    SHAPE ABUTMENT ;
    PORT
      LAYER met2 ;
      RECT 516.050 0.000 516.190 0.420 ;
    END
  END r0_rd_out[60]
  PIN r0_rd_out[61]
    DIRECTION OUTPUT ;
    USE SIGNAL ;
    SHAPE ABUTMENT ;
    PORT
      LAYER met2 ;
      RECT 520.190 0.000 520.330 0.420 ;
    END
  END r0_rd_out[61]
  PIN r0_rd_out[62]
    DIRECTION OUTPUT ;
    USE SIGNAL ;
    SHAPE ABUTMENT ;
    PORT
      LAYER met2 ;
      RECT 524.330 0.000 524.470 0.420 ;
    END
  END r0_rd_out[62]
  PIN r0_rd_out[63]
    DIRECTION OUTPUT ;
    USE SIGNAL ;
    SHAPE ABUTMENT ;
    PORT
      LAYER met2 ;
      RECT 528.470 0.000 528.610 0.420 ;
    END
  END r0_rd_out[63]
  PIN r0_rd_out[64]
    DIRECTION OUTPUT ;
    USE SIGNAL ;
    SHAPE ABUTMENT ;
    PORT
      LAYER met2 ;
      RECT 267.650 456.540 267.790 456.960 ;
    END
  END r0_rd_out[64]
  PIN r0_rd_out[65]
    DIRECTION OUTPUT ;
    USE SIGNAL ;
    SHAPE ABUTMENT ;
    PORT
      LAYER met2 ;
      RECT 271.790 456.540 271.930 456.960 ;
    END
  END r0_rd_out[65]
  PIN r0_rd_out[66]
    DIRECTION OUTPUT ;
    USE SIGNAL ;
    SHAPE ABUTMENT ;
    PORT
      LAYER met2 ;
      RECT 275.930 456.540 276.070 456.960 ;
    END
  END r0_rd_out[66]
  PIN r0_rd_out[67]
    DIRECTION OUTPUT ;
    USE SIGNAL ;
    SHAPE ABUTMENT ;
    PORT
      LAYER met2 ;
      RECT 280.070 456.540 280.210 456.960 ;
    END
  END r0_rd_out[67]
  PIN r0_rd_out[68]
    DIRECTION OUTPUT ;
    USE SIGNAL ;
    SHAPE ABUTMENT ;
    PORT
      LAYER met2 ;
      RECT 284.210 456.540 284.350 456.960 ;
    END
  END r0_rd_out[68]
  PIN r0_rd_out[69]
    DIRECTION OUTPUT ;
    USE SIGNAL ;
    SHAPE ABUTMENT ;
    PORT
      LAYER met2 ;
      RECT 288.350 456.540 288.490 456.960 ;
    END
  END r0_rd_out[69]
  PIN r0_rd_out[70]
    DIRECTION OUTPUT ;
    USE SIGNAL ;
    SHAPE ABUTMENT ;
    PORT
      LAYER met2 ;
      RECT 292.490 456.540 292.630 456.960 ;
    END
  END r0_rd_out[70]
  PIN r0_rd_out[71]
    DIRECTION OUTPUT ;
    USE SIGNAL ;
    SHAPE ABUTMENT ;
    PORT
      LAYER met2 ;
      RECT 296.630 456.540 296.770 456.960 ;
    END
  END r0_rd_out[71]
  PIN r0_rd_out[72]
    DIRECTION OUTPUT ;
    USE SIGNAL ;
    SHAPE ABUTMENT ;
    PORT
      LAYER met2 ;
      RECT 300.770 456.540 300.910 456.960 ;
    END
  END r0_rd_out[72]
  PIN r0_rd_out[73]
    DIRECTION OUTPUT ;
    USE SIGNAL ;
    SHAPE ABUTMENT ;
    PORT
      LAYER met2 ;
      RECT 304.910 456.540 305.050 456.960 ;
    END
  END r0_rd_out[73]
  PIN r0_rd_out[74]
    DIRECTION OUTPUT ;
    USE SIGNAL ;
    SHAPE ABUTMENT ;
    PORT
      LAYER met2 ;
      RECT 309.050 456.540 309.190 456.960 ;
    END
  END r0_rd_out[74]
  PIN r0_rd_out[75]
    DIRECTION OUTPUT ;
    USE SIGNAL ;
    SHAPE ABUTMENT ;
    PORT
      LAYER met2 ;
      RECT 313.190 456.540 313.330 456.960 ;
    END
  END r0_rd_out[75]
  PIN r0_rd_out[76]
    DIRECTION OUTPUT ;
    USE SIGNAL ;
    SHAPE ABUTMENT ;
    PORT
      LAYER met2 ;
      RECT 317.330 456.540 317.470 456.960 ;
    END
  END r0_rd_out[76]
  PIN r0_rd_out[77]
    DIRECTION OUTPUT ;
    USE SIGNAL ;
    SHAPE ABUTMENT ;
    PORT
      LAYER met2 ;
      RECT 321.470 456.540 321.610 456.960 ;
    END
  END r0_rd_out[77]
  PIN r0_rd_out[78]
    DIRECTION OUTPUT ;
    USE SIGNAL ;
    SHAPE ABUTMENT ;
    PORT
      LAYER met2 ;
      RECT 325.610 456.540 325.750 456.960 ;
    END
  END r0_rd_out[78]
  PIN r0_rd_out[79]
    DIRECTION OUTPUT ;
    USE SIGNAL ;
    SHAPE ABUTMENT ;
    PORT
      LAYER met2 ;
      RECT 329.750 456.540 329.890 456.960 ;
    END
  END r0_rd_out[79]
  PIN r0_rd_out[80]
    DIRECTION OUTPUT ;
    USE SIGNAL ;
    SHAPE ABUTMENT ;
    PORT
      LAYER met2 ;
      RECT 333.890 456.540 334.030 456.960 ;
    END
  END r0_rd_out[80]
  PIN r0_rd_out[81]
    DIRECTION OUTPUT ;
    USE SIGNAL ;
    SHAPE ABUTMENT ;
    PORT
      LAYER met2 ;
      RECT 338.030 456.540 338.170 456.960 ;
    END
  END r0_rd_out[81]
  PIN r0_rd_out[82]
    DIRECTION OUTPUT ;
    USE SIGNAL ;
    SHAPE ABUTMENT ;
    PORT
      LAYER met2 ;
      RECT 342.170 456.540 342.310 456.960 ;
    END
  END r0_rd_out[82]
  PIN r0_rd_out[83]
    DIRECTION OUTPUT ;
    USE SIGNAL ;
    SHAPE ABUTMENT ;
    PORT
      LAYER met2 ;
      RECT 346.310 456.540 346.450 456.960 ;
    END
  END r0_rd_out[83]
  PIN r0_rd_out[84]
    DIRECTION OUTPUT ;
    USE SIGNAL ;
    SHAPE ABUTMENT ;
    PORT
      LAYER met2 ;
      RECT 350.450 456.540 350.590 456.960 ;
    END
  END r0_rd_out[84]
  PIN r0_rd_out[85]
    DIRECTION OUTPUT ;
    USE SIGNAL ;
    SHAPE ABUTMENT ;
    PORT
      LAYER met2 ;
      RECT 354.590 456.540 354.730 456.960 ;
    END
  END r0_rd_out[85]
  PIN r0_rd_out[86]
    DIRECTION OUTPUT ;
    USE SIGNAL ;
    SHAPE ABUTMENT ;
    PORT
      LAYER met2 ;
      RECT 358.730 456.540 358.870 456.960 ;
    END
  END r0_rd_out[86]
  PIN r0_rd_out[87]
    DIRECTION OUTPUT ;
    USE SIGNAL ;
    SHAPE ABUTMENT ;
    PORT
      LAYER met2 ;
      RECT 362.870 456.540 363.010 456.960 ;
    END
  END r0_rd_out[87]
  PIN r0_rd_out[88]
    DIRECTION OUTPUT ;
    USE SIGNAL ;
    SHAPE ABUTMENT ;
    PORT
      LAYER met2 ;
      RECT 367.010 456.540 367.150 456.960 ;
    END
  END r0_rd_out[88]
  PIN r0_rd_out[89]
    DIRECTION OUTPUT ;
    USE SIGNAL ;
    SHAPE ABUTMENT ;
    PORT
      LAYER met2 ;
      RECT 371.150 456.540 371.290 456.960 ;
    END
  END r0_rd_out[89]
  PIN r0_rd_out[90]
    DIRECTION OUTPUT ;
    USE SIGNAL ;
    SHAPE ABUTMENT ;
    PORT
      LAYER met2 ;
      RECT 375.290 456.540 375.430 456.960 ;
    END
  END r0_rd_out[90]
  PIN r0_rd_out[91]
    DIRECTION OUTPUT ;
    USE SIGNAL ;
    SHAPE ABUTMENT ;
    PORT
      LAYER met2 ;
      RECT 379.430 456.540 379.570 456.960 ;
    END
  END r0_rd_out[91]
  PIN r0_rd_out[92]
    DIRECTION OUTPUT ;
    USE SIGNAL ;
    SHAPE ABUTMENT ;
    PORT
      LAYER met2 ;
      RECT 383.570 456.540 383.710 456.960 ;
    END
  END r0_rd_out[92]
  PIN r0_rd_out[93]
    DIRECTION OUTPUT ;
    USE SIGNAL ;
    SHAPE ABUTMENT ;
    PORT
      LAYER met2 ;
      RECT 387.710 456.540 387.850 456.960 ;
    END
  END r0_rd_out[93]
  PIN r0_rd_out[94]
    DIRECTION OUTPUT ;
    USE SIGNAL ;
    SHAPE ABUTMENT ;
    PORT
      LAYER met2 ;
      RECT 391.850 456.540 391.990 456.960 ;
    END
  END r0_rd_out[94]
  PIN r0_rd_out[95]
    DIRECTION OUTPUT ;
    USE SIGNAL ;
    SHAPE ABUTMENT ;
    PORT
      LAYER met2 ;
      RECT 395.990 456.540 396.130 456.960 ;
    END
  END r0_rd_out[95]
  PIN r0_rd_out[96]
    DIRECTION OUTPUT ;
    USE SIGNAL ;
    SHAPE ABUTMENT ;
    PORT
      LAYER met2 ;
      RECT 400.130 456.540 400.270 456.960 ;
    END
  END r0_rd_out[96]
  PIN r0_rd_out[97]
    DIRECTION OUTPUT ;
    USE SIGNAL ;
    SHAPE ABUTMENT ;
    PORT
      LAYER met2 ;
      RECT 404.270 456.540 404.410 456.960 ;
    END
  END r0_rd_out[97]
  PIN r0_rd_out[98]
    DIRECTION OUTPUT ;
    USE SIGNAL ;
    SHAPE ABUTMENT ;
    PORT
      LAYER met2 ;
      RECT 408.410 456.540 408.550 456.960 ;
    END
  END r0_rd_out[98]
  PIN r0_rd_out[99]
    DIRECTION OUTPUT ;
    USE SIGNAL ;
    SHAPE ABUTMENT ;
    PORT
      LAYER met2 ;
      RECT 412.550 456.540 412.690 456.960 ;
    END
  END r0_rd_out[99]
  PIN r0_rd_out[100]
    DIRECTION OUTPUT ;
    USE SIGNAL ;
    SHAPE ABUTMENT ;
    PORT
      LAYER met2 ;
      RECT 416.690 456.540 416.830 456.960 ;
    END
  END r0_rd_out[100]
  PIN r0_rd_out[101]
    DIRECTION OUTPUT ;
    USE SIGNAL ;
    SHAPE ABUTMENT ;
    PORT
      LAYER met2 ;
      RECT 420.830 456.540 420.970 456.960 ;
    END
  END r0_rd_out[101]
  PIN r0_rd_out[102]
    DIRECTION OUTPUT ;
    USE SIGNAL ;
    SHAPE ABUTMENT ;
    PORT
      LAYER met2 ;
      RECT 424.970 456.540 425.110 456.960 ;
    END
  END r0_rd_out[102]
  PIN r0_rd_out[103]
    DIRECTION OUTPUT ;
    USE SIGNAL ;
    SHAPE ABUTMENT ;
    PORT
      LAYER met2 ;
      RECT 429.110 456.540 429.250 456.960 ;
    END
  END r0_rd_out[103]
  PIN r0_rd_out[104]
    DIRECTION OUTPUT ;
    USE SIGNAL ;
    SHAPE ABUTMENT ;
    PORT
      LAYER met2 ;
      RECT 433.250 456.540 433.390 456.960 ;
    END
  END r0_rd_out[104]
  PIN r0_rd_out[105]
    DIRECTION OUTPUT ;
    USE SIGNAL ;
    SHAPE ABUTMENT ;
    PORT
      LAYER met2 ;
      RECT 437.390 456.540 437.530 456.960 ;
    END
  END r0_rd_out[105]
  PIN r0_rd_out[106]
    DIRECTION OUTPUT ;
    USE SIGNAL ;
    SHAPE ABUTMENT ;
    PORT
      LAYER met2 ;
      RECT 441.530 456.540 441.670 456.960 ;
    END
  END r0_rd_out[106]
  PIN r0_rd_out[107]
    DIRECTION OUTPUT ;
    USE SIGNAL ;
    SHAPE ABUTMENT ;
    PORT
      LAYER met2 ;
      RECT 445.670 456.540 445.810 456.960 ;
    END
  END r0_rd_out[107]
  PIN r0_rd_out[108]
    DIRECTION OUTPUT ;
    USE SIGNAL ;
    SHAPE ABUTMENT ;
    PORT
      LAYER met2 ;
      RECT 449.810 456.540 449.950 456.960 ;
    END
  END r0_rd_out[108]
  PIN r0_rd_out[109]
    DIRECTION OUTPUT ;
    USE SIGNAL ;
    SHAPE ABUTMENT ;
    PORT
      LAYER met2 ;
      RECT 453.950 456.540 454.090 456.960 ;
    END
  END r0_rd_out[109]
  PIN r0_rd_out[110]
    DIRECTION OUTPUT ;
    USE SIGNAL ;
    SHAPE ABUTMENT ;
    PORT
      LAYER met2 ;
      RECT 458.090 456.540 458.230 456.960 ;
    END
  END r0_rd_out[110]
  PIN r0_rd_out[111]
    DIRECTION OUTPUT ;
    USE SIGNAL ;
    SHAPE ABUTMENT ;
    PORT
      LAYER met2 ;
      RECT 462.230 456.540 462.370 456.960 ;
    END
  END r0_rd_out[111]
  PIN r0_rd_out[112]
    DIRECTION OUTPUT ;
    USE SIGNAL ;
    SHAPE ABUTMENT ;
    PORT
      LAYER met2 ;
      RECT 466.370 456.540 466.510 456.960 ;
    END
  END r0_rd_out[112]
  PIN r0_rd_out[113]
    DIRECTION OUTPUT ;
    USE SIGNAL ;
    SHAPE ABUTMENT ;
    PORT
      LAYER met2 ;
      RECT 470.510 456.540 470.650 456.960 ;
    END
  END r0_rd_out[113]
  PIN r0_rd_out[114]
    DIRECTION OUTPUT ;
    USE SIGNAL ;
    SHAPE ABUTMENT ;
    PORT
      LAYER met2 ;
      RECT 474.650 456.540 474.790 456.960 ;
    END
  END r0_rd_out[114]
  PIN r0_rd_out[115]
    DIRECTION OUTPUT ;
    USE SIGNAL ;
    SHAPE ABUTMENT ;
    PORT
      LAYER met2 ;
      RECT 478.790 456.540 478.930 456.960 ;
    END
  END r0_rd_out[115]
  PIN r0_rd_out[116]
    DIRECTION OUTPUT ;
    USE SIGNAL ;
    SHAPE ABUTMENT ;
    PORT
      LAYER met2 ;
      RECT 482.930 456.540 483.070 456.960 ;
    END
  END r0_rd_out[116]
  PIN r0_rd_out[117]
    DIRECTION OUTPUT ;
    USE SIGNAL ;
    SHAPE ABUTMENT ;
    PORT
      LAYER met2 ;
      RECT 487.070 456.540 487.210 456.960 ;
    END
  END r0_rd_out[117]
  PIN r0_rd_out[118]
    DIRECTION OUTPUT ;
    USE SIGNAL ;
    SHAPE ABUTMENT ;
    PORT
      LAYER met2 ;
      RECT 491.210 456.540 491.350 456.960 ;
    END
  END r0_rd_out[118]
  PIN r0_rd_out[119]
    DIRECTION OUTPUT ;
    USE SIGNAL ;
    SHAPE ABUTMENT ;
    PORT
      LAYER met2 ;
      RECT 495.350 456.540 495.490 456.960 ;
    END
  END r0_rd_out[119]
  PIN r0_rd_out[120]
    DIRECTION OUTPUT ;
    USE SIGNAL ;
    SHAPE ABUTMENT ;
    PORT
      LAYER met2 ;
      RECT 499.490 456.540 499.630 456.960 ;
    END
  END r0_rd_out[120]
  PIN r0_rd_out[121]
    DIRECTION OUTPUT ;
    USE SIGNAL ;
    SHAPE ABUTMENT ;
    PORT
      LAYER met2 ;
      RECT 503.630 456.540 503.770 456.960 ;
    END
  END r0_rd_out[121]
  PIN r0_rd_out[122]
    DIRECTION OUTPUT ;
    USE SIGNAL ;
    SHAPE ABUTMENT ;
    PORT
      LAYER met2 ;
      RECT 507.770 456.540 507.910 456.960 ;
    END
  END r0_rd_out[122]
  PIN r0_rd_out[123]
    DIRECTION OUTPUT ;
    USE SIGNAL ;
    SHAPE ABUTMENT ;
    PORT
      LAYER met2 ;
      RECT 511.910 456.540 512.050 456.960 ;
    END
  END r0_rd_out[123]
  PIN r0_rd_out[124]
    DIRECTION OUTPUT ;
    USE SIGNAL ;
    SHAPE ABUTMENT ;
    PORT
      LAYER met2 ;
      RECT 516.050 456.540 516.190 456.960 ;
    END
  END r0_rd_out[124]
  PIN r0_rd_out[125]
    DIRECTION OUTPUT ;
    USE SIGNAL ;
    SHAPE ABUTMENT ;
    PORT
      LAYER met2 ;
      RECT 520.190 456.540 520.330 456.960 ;
    END
  END r0_rd_out[125]
  PIN r0_rd_out[126]
    DIRECTION OUTPUT ;
    USE SIGNAL ;
    SHAPE ABUTMENT ;
    PORT
      LAYER met2 ;
      RECT 524.330 456.540 524.470 456.960 ;
    END
  END r0_rd_out[126]
  PIN r0_rd_out[127]
    DIRECTION OUTPUT ;
    USE SIGNAL ;
    SHAPE ABUTMENT ;
    PORT
      LAYER met2 ;
      RECT 528.470 456.540 528.610 456.960 ;
    END
  END r0_rd_out[127]
  PIN w0_addr_in[0]
    DIRECTION INPUT ;
    USE SIGNAL ;
    SHAPE ABUTMENT ;
    PORT
      LAYER met3 ;
      RECT 0.000 395.610 0.900 395.910 ;
    END
  END w0_addr_in[0]
  PIN w0_addr_in[1]
    DIRECTION INPUT ;
    USE SIGNAL ;
    SHAPE ABUTMENT ;
    PORT
      LAYER met3 ;
      RECT 0.000 401.730 0.900 402.030 ;
    END
  END w0_addr_in[1]
  PIN w0_addr_in[2]
    DIRECTION INPUT ;
    USE SIGNAL ;
    SHAPE ABUTMENT ;
    PORT
      LAYER met3 ;
      RECT 0.000 407.850 0.900 408.150 ;
    END
  END w0_addr_in[2]
  PIN w0_addr_in[3]
    DIRECTION INPUT ;
    USE SIGNAL ;
    SHAPE ABUTMENT ;
    PORT
      LAYER met3 ;
      RECT 560.760 395.610 561.660 395.910 ;
    END
  END w0_addr_in[3]
  PIN w0_addr_in[4]
    DIRECTION INPUT ;
    USE SIGNAL ;
    SHAPE ABUTMENT ;
    PORT
      LAYER met3 ;
      RECT 560.760 401.730 561.660 402.030 ;
    END
  END w0_addr_in[4]
  PIN w0_addr_in[5]
    DIRECTION INPUT ;
    USE SIGNAL ;
    SHAPE ABUTMENT ;
    PORT
      LAYER met3 ;
      RECT 560.760 407.850 561.660 408.150 ;
    END
  END w0_addr_in[5]
  PIN r0_addr_in[0]
    DIRECTION INPUT ;
    USE SIGNAL ;
    SHAPE ABUTMENT ;
    PORT
      LAYER met3 ;
      RECT 0.000 413.970 0.900 414.270 ;
    END
  END r0_addr_in[0]
  PIN r0_addr_in[1]
    DIRECTION INPUT ;
    USE SIGNAL ;
    SHAPE ABUTMENT ;
    PORT
      LAYER met3 ;
      RECT 0.000 420.090 0.900 420.390 ;
    END
  END r0_addr_in[1]
  PIN r0_addr_in[2]
    DIRECTION INPUT ;
    USE SIGNAL ;
    SHAPE ABUTMENT ;
    PORT
      LAYER met3 ;
      RECT 0.000 426.210 0.900 426.510 ;
    END
  END r0_addr_in[2]
  PIN r0_addr_in[3]
    DIRECTION INPUT ;
    USE SIGNAL ;
    SHAPE ABUTMENT ;
    PORT
      LAYER met3 ;
      RECT 560.760 413.970 561.660 414.270 ;
    END
  END r0_addr_in[3]
  PIN r0_addr_in[4]
    DIRECTION INPUT ;
    USE SIGNAL ;
    SHAPE ABUTMENT ;
    PORT
      LAYER met3 ;
      RECT 560.760 420.090 561.660 420.390 ;
    END
  END r0_addr_in[4]
  PIN r0_addr_in[5]
    DIRECTION INPUT ;
    USE SIGNAL ;
    SHAPE ABUTMENT ;
    PORT
      LAYER met3 ;
      RECT 560.760 426.210 561.660 426.510 ;
    END
  END r0_addr_in[5]
  PIN w0_we_in
    DIRECTION INPUT ;
    USE SIGNAL ;
    SHAPE ABUTMENT ;
    PORT
      LAYER met2 ;
      RECT 532.610 456.540 532.750 456.960 ;
    END
  END w0_we_in
  PIN w0_ce_in
    DIRECTION INPUT ;
    USE SIGNAL ;
    SHAPE ABUTMENT ;
    PORT
      LAYER met2 ;
      RECT 536.750 456.540 536.890 456.960 ;
    END
  END w0_ce_in
  PIN w0_clk
    DIRECTION INPUT ;
    USE SIGNAL ;
    SHAPE ABUTMENT ;
    PORT
      LAYER met2 ;
      RECT 540.890 456.540 541.030 456.960 ;
    END
  END w0_clk
  PIN r0_ce_in
    DIRECTION INPUT ;
    USE SIGNAL ;
    SHAPE ABUTMENT ;
    PORT
      LAYER met2 ;
      RECT 545.030 456.540 545.170 456.960 ;
    END
  END r0_ce_in
  PIN r0_clk
    DIRECTION INPUT ;
    USE SIGNAL ;
    SHAPE ABUTMENT ;
    PORT
      LAYER met2 ;
      RECT 549.170 456.540 549.310 456.960 ;
    END
  END r0_clk
  PIN VSS
    DIRECTION INOUT ;
    USE GROUND ;
    PORT
      LAYER met4 ;
      RECT 2.160 4.080 3.360 452.880 ;
      RECT 13.040 4.080 14.240 452.880 ;
      RECT 23.920 4.080 25.120 452.880 ;
      RECT 34.800 4.080 36.000 452.880 ;
      RECT 45.680 4.080 46.880 452.880 ;
      RECT 56.560 4.080 57.760 452.880 ;
      RECT 67.440 4.080 68.640 452.880 ;
      RECT 78.320 4.080 79.520 452.880 ;
      RECT 89.200 4.080 90.400 452.880 ;
      RECT 100.080 4.080 101.280 452.880 ;
      RECT 110.960 4.080 112.160 452.880 ;
      RECT 121.840 4.080 123.040 452.880 ;
      RECT 132.720 4.080 133.920 452.880 ;
      RECT 143.600 4.080 144.800 452.880 ;
      RECT 154.480 4.080 155.680 452.880 ;
      RECT 165.360 4.080 166.560 452.880 ;
      RECT 176.240 4.080 177.440 452.880 ;
      RECT 187.120 4.080 188.320 452.880 ;
      RECT 198.000 4.080 199.200 452.880 ;
      RECT 208.880 4.080 210.080 452.880 ;
      RECT 219.760 4.080 220.960 452.880 ;
      RECT 230.640 4.080 231.840 452.880 ;
      RECT 241.520 4.080 242.720 452.880 ;
      RECT 252.400 4.080 253.600 452.880 ;
      RECT 263.280 4.080 264.480 452.880 ;
      RECT 274.160 4.080 275.360 452.880 ;
      RECT 285.040 4.080 286.240 452.880 ;
      RECT 295.920 4.080 297.120 452.880 ;
      RECT 306.800 4.080 308.000 452.880 ;
      RECT 317.680 4.080 318.880 452.880 ;
      RECT 328.560 4.080 329.760 452.880 ;
      RECT 339.440 4.080 340.640 452.880 ;
      RECT 350.320 4.080 351.520 452.880 ;
      RECT 361.200 4.080 362.400 452.880 ;
      RECT 372.080 4.080 373.280 452.880 ;
      RECT 382.960 4.080 384.160 452.880 ;
      RECT 393.840 4.080 395.040 452.880 ;
      RECT 404.720 4.080 405.920 452.880 ;
      RECT 415.600 4.080 416.800 452.880 ;
      RECT 426.480 4.080 427.680 452.880 ;
      RECT 437.360 4.080 438.560 452.880 ;
      RECT 448.240 4.080 449.440 452.880 ;
      RECT 459.120 4.080 460.320 452.880 ;
      RECT 470.000 4.080 471.200 452.880 ;
      RECT 480.880 4.080 482.080 452.880 ;
      RECT 491.760 4.080 492.960 452.880 ;
      RECT 502.640 4.080 503.840 452.880 ;
      RECT 513.520 4.080 514.720 452.880 ;
      RECT 524.400 4.080 525.600 452.880 ;
      RECT 535.280 4.080 536.480 452.880 ;
      RECT 546.160 4.080 547.360 452.880 ;
      RECT 557.040 4.080 558.240 452.880 ;
    END
  END VSS
  PIN VDD
    DIRECTION INOUT ;
    USE POWER ;
    PORT
      LAYER met4 ;
      RECT 7.600 4.080 8.800 452.880 ;
      RECT 18.480 4.080 19.680 452.880 ;
      RECT 29.360 4.080 30.560 452.880 ;
      RECT 40.240 4.080 41.440 452.880 ;
      RECT 51.120 4.080 52.320 452.880 ;
      RECT 62.000 4.080 63.200 452.880 ;
      RECT 72.880 4.080 74.080 452.880 ;
      RECT 83.760 4.080 84.960 452.880 ;
      RECT 94.640 4.080 95.840 452.880 ;
      RECT 105.520 4.080 106.720 452.880 ;
      RECT 116.400 4.080 117.600 452.880 ;
      RECT 127.280 4.080 128.480 452.880 ;
      RECT 138.160 4.080 139.360 452.880 ;
      RECT 149.040 4.080 150.240 452.880 ;
      RECT 159.920 4.080 161.120 452.880 ;
      RECT 170.800 4.080 172.000 452.880 ;
      RECT 181.680 4.080 182.880 452.880 ;
      RECT 192.560 4.080 193.760 452.880 ;
      RECT 203.440 4.080 204.640 452.880 ;
      RECT 214.320 4.080 215.520 452.880 ;
      RECT 225.200 4.080 226.400 452.880 ;
      RECT 236.080 4.080 237.280 452.880 ;
      RECT 246.960 4.080 248.160 452.880 ;
      RECT 257.840 4.080 259.040 452.880 ;
      RECT 268.720 4.080 269.920 452.880 ;
      RECT 279.600 4.080 280.800 452.880 ;
      RECT 290.480 4.080 291.680 452.880 ;
      RECT 301.360 4.080 302.560 452.880 ;
      RECT 312.240 4.080 313.440 452.880 ;
      RECT 323.120 4.080 324.320 452.880 ;
      RECT 334.000 4.080 335.200 452.880 ;
      RECT 344.880 4.080 346.080 452.880 ;
      RECT 355.760 4.080 356.960 452.880 ;
      RECT 366.640 4.080 367.840 452.880 ;
      RECT 377.520 4.080 378.720 452.880 ;
      RECT 388.400 4.080 389.600 452.880 ;
      RECT 399.280 4.080 400.480 452.880 ;
      RECT 410.160 4.080 411.360 452.880 ;
      RECT 421.040 4.080 422.240 452.880 ;
      RECT 431.920 4.080 433.120 452.880 ;
      RECT 442.800 4.080 444.000 452.880 ;
      RECT 453.680 4.080 454.880 452.880 ;
      RECT 464.560 4.080 465.760 452.880 ;
      RECT 475.440 4.080 476.640 452.880 ;
      RECT 486.320 4.080 487.520 452.880 ;
      RECT 497.200 4.080 498.400 452.880 ;
      RECT 508.080 4.080 509.280 452.880 ;
      RECT 518.960 4.080 520.160 452.880 ;
      RECT 529.840 4.080 531.040 452.880 ;
      RECT 540.720 4.080 541.920 452.880 ;
      RECT 551.600 4.080 552.800 452.880 ;
    END
  END VDD
  OBS
    LAYER met1 ;
    RECT 0 0 561.660 456.960 ;
    LAYER met2 ;
    RECT 0 0 561.660 456.960 ;
    LAYER met3 ;
    RECT 0 0 561.660 456.960 ;
    LAYER met4 ;
    RECT 0 0 561.660 456.960 ;
  END
END fakeram_128x64_1r1w

END LIBRARY
